VERSION 5.7 ;
BUSBITCHARS "[]" ;
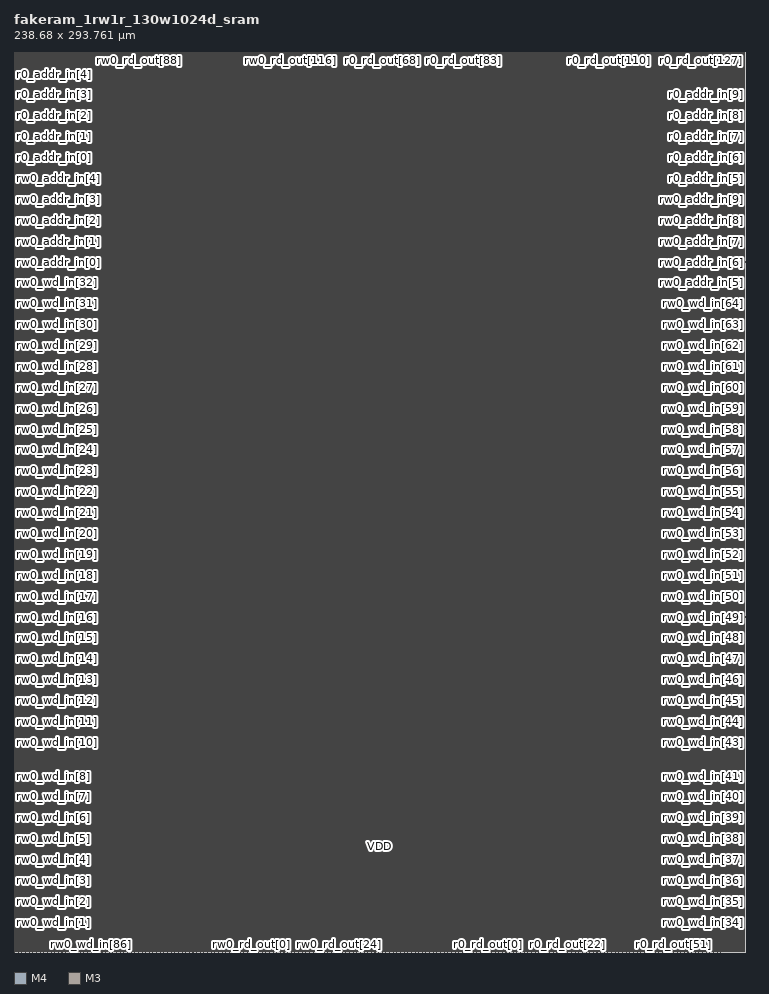
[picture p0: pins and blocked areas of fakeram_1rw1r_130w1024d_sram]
MACRO fakeram_1rw1r_130w1024d_sram
  FOREIGN fakeram_1rw1r_130w1024d_sram 0 0 ;
  SYMMETRY X Y R90 ;
  SIZE 238.680 BY 293.761 ;
  CLASS BLOCK ;
  PIN rw0_wd_in[0]
    DIRECTION INPUT ;
    USE SIGNAL ;
    SHAPE ABUTMENT ;
    PORT
      LAYER M4 ;
      RECT 0.000 0.276 0.072 0.300 ;
    END
  END rw0_wd_in[0]
  PIN rw0_wd_in[1]
    DIRECTION INPUT ;
    USE SIGNAL ;
    SHAPE ABUTMENT ;
    PORT
      LAYER M4 ;
      RECT 0.000 7.092 0.072 7.116 ;
    END
  END rw0_wd_in[1]
  PIN rw0_wd_in[2]
    DIRECTION INPUT ;
    USE SIGNAL ;
    SHAPE ABUTMENT ;
    PORT
      LAYER M4 ;
      RECT 0.000 13.908 0.072 13.932 ;
    END
  END rw0_wd_in[2]
  PIN rw0_wd_in[3]
    DIRECTION INPUT ;
    USE SIGNAL ;
    SHAPE ABUTMENT ;
    PORT
      LAYER M4 ;
      RECT 0.000 20.724 0.072 20.748 ;
    END
  END rw0_wd_in[3]
  PIN rw0_wd_in[4]
    DIRECTION INPUT ;
    USE SIGNAL ;
    SHAPE ABUTMENT ;
    PORT
      LAYER M4 ;
      RECT 0.000 27.540 0.072 27.564 ;
    END
  END rw0_wd_in[4]
  PIN rw0_wd_in[5]
    DIRECTION INPUT ;
    USE SIGNAL ;
    SHAPE ABUTMENT ;
    PORT
      LAYER M4 ;
      RECT 0.000 34.356 0.072 34.380 ;
    END
  END rw0_wd_in[5]
  PIN rw0_wd_in[6]
    DIRECTION INPUT ;
    USE SIGNAL ;
    SHAPE ABUTMENT ;
    PORT
      LAYER M4 ;
      RECT 0.000 41.172 0.072 41.196 ;
    END
  END rw0_wd_in[6]
  PIN rw0_wd_in[7]
    DIRECTION INPUT ;
    USE SIGNAL ;
    SHAPE ABUTMENT ;
    PORT
      LAYER M4 ;
      RECT 0.000 47.988 0.072 48.012 ;
    END
  END rw0_wd_in[7]
  PIN rw0_wd_in[8]
    DIRECTION INPUT ;
    USE SIGNAL ;
    SHAPE ABUTMENT ;
    PORT
      LAYER M4 ;
      RECT 0.000 54.804 0.072 54.828 ;
    END
  END rw0_wd_in[8]
  PIN rw0_wd_in[9]
    DIRECTION INPUT ;
    USE SIGNAL ;
    SHAPE ABUTMENT ;
    PORT
      LAYER M4 ;
      RECT 0.000 61.620 0.072 61.644 ;
    END
  END rw0_wd_in[9]
  PIN rw0_wd_in[10]
    DIRECTION INPUT ;
    USE SIGNAL ;
    SHAPE ABUTMENT ;
    PORT
      LAYER M4 ;
      RECT 0.000 68.436 0.072 68.460 ;
    END
  END rw0_wd_in[10]
  PIN rw0_wd_in[11]
    DIRECTION INPUT ;
    USE SIGNAL ;
    SHAPE ABUTMENT ;
    PORT
      LAYER M4 ;
      RECT 0.000 75.252 0.072 75.276 ;
    END
  END rw0_wd_in[11]
  PIN rw0_wd_in[12]
    DIRECTION INPUT ;
    USE SIGNAL ;
    SHAPE ABUTMENT ;
    PORT
      LAYER M4 ;
      RECT 0.000 82.068 0.072 82.092 ;
    END
  END rw0_wd_in[12]
  PIN rw0_wd_in[13]
    DIRECTION INPUT ;
    USE SIGNAL ;
    SHAPE ABUTMENT ;
    PORT
      LAYER M4 ;
      RECT 0.000 88.884 0.072 88.908 ;
    END
  END rw0_wd_in[13]
  PIN rw0_wd_in[14]
    DIRECTION INPUT ;
    USE SIGNAL ;
    SHAPE ABUTMENT ;
    PORT
      LAYER M4 ;
      RECT 0.000 95.700 0.072 95.724 ;
    END
  END rw0_wd_in[14]
  PIN rw0_wd_in[15]
    DIRECTION INPUT ;
    USE SIGNAL ;
    SHAPE ABUTMENT ;
    PORT
      LAYER M4 ;
      RECT 0.000 102.516 0.072 102.540 ;
    END
  END rw0_wd_in[15]
  PIN rw0_wd_in[16]
    DIRECTION INPUT ;
    USE SIGNAL ;
    SHAPE ABUTMENT ;
    PORT
      LAYER M4 ;
      RECT 0.000 109.332 0.072 109.356 ;
    END
  END rw0_wd_in[16]
  PIN rw0_wd_in[17]
    DIRECTION INPUT ;
    USE SIGNAL ;
    SHAPE ABUTMENT ;
    PORT
      LAYER M4 ;
      RECT 0.000 116.148 0.072 116.172 ;
    END
  END rw0_wd_in[17]
  PIN rw0_wd_in[18]
    DIRECTION INPUT ;
    USE SIGNAL ;
    SHAPE ABUTMENT ;
    PORT
      LAYER M4 ;
      RECT 0.000 122.964 0.072 122.988 ;
    END
  END rw0_wd_in[18]
  PIN rw0_wd_in[19]
    DIRECTION INPUT ;
    USE SIGNAL ;
    SHAPE ABUTMENT ;
    PORT
      LAYER M4 ;
      RECT 0.000 129.780 0.072 129.804 ;
    END
  END rw0_wd_in[19]
  PIN rw0_wd_in[20]
    DIRECTION INPUT ;
    USE SIGNAL ;
    SHAPE ABUTMENT ;
    PORT
      LAYER M4 ;
      RECT 0.000 136.596 0.072 136.620 ;
    END
  END rw0_wd_in[20]
  PIN rw0_wd_in[21]
    DIRECTION INPUT ;
    USE SIGNAL ;
    SHAPE ABUTMENT ;
    PORT
      LAYER M4 ;
      RECT 0.000 143.412 0.072 143.436 ;
    END
  END rw0_wd_in[21]
  PIN rw0_wd_in[22]
    DIRECTION INPUT ;
    USE SIGNAL ;
    SHAPE ABUTMENT ;
    PORT
      LAYER M4 ;
      RECT 0.000 150.228 0.072 150.252 ;
    END
  END rw0_wd_in[22]
  PIN rw0_wd_in[23]
    DIRECTION INPUT ;
    USE SIGNAL ;
    SHAPE ABUTMENT ;
    PORT
      LAYER M4 ;
      RECT 0.000 157.044 0.072 157.068 ;
    END
  END rw0_wd_in[23]
  PIN rw0_wd_in[24]
    DIRECTION INPUT ;
    USE SIGNAL ;
    SHAPE ABUTMENT ;
    PORT
      LAYER M4 ;
      RECT 0.000 163.860 0.072 163.884 ;
    END
  END rw0_wd_in[24]
  PIN rw0_wd_in[25]
    DIRECTION INPUT ;
    USE SIGNAL ;
    SHAPE ABUTMENT ;
    PORT
      LAYER M4 ;
      RECT 0.000 170.676 0.072 170.700 ;
    END
  END rw0_wd_in[25]
  PIN rw0_wd_in[26]
    DIRECTION INPUT ;
    USE SIGNAL ;
    SHAPE ABUTMENT ;
    PORT
      LAYER M4 ;
      RECT 0.000 177.492 0.072 177.516 ;
    END
  END rw0_wd_in[26]
  PIN rw0_wd_in[27]
    DIRECTION INPUT ;
    USE SIGNAL ;
    SHAPE ABUTMENT ;
    PORT
      LAYER M4 ;
      RECT 0.000 184.308 0.072 184.332 ;
    END
  END rw0_wd_in[27]
  PIN rw0_wd_in[28]
    DIRECTION INPUT ;
    USE SIGNAL ;
    SHAPE ABUTMENT ;
    PORT
      LAYER M4 ;
      RECT 0.000 191.124 0.072 191.148 ;
    END
  END rw0_wd_in[28]
  PIN rw0_wd_in[29]
    DIRECTION INPUT ;
    USE SIGNAL ;
    SHAPE ABUTMENT ;
    PORT
      LAYER M4 ;
      RECT 0.000 197.940 0.072 197.964 ;
    END
  END rw0_wd_in[29]
  PIN rw0_wd_in[30]
    DIRECTION INPUT ;
    USE SIGNAL ;
    SHAPE ABUTMENT ;
    PORT
      LAYER M4 ;
      RECT 0.000 204.756 0.072 204.780 ;
    END
  END rw0_wd_in[30]
  PIN rw0_wd_in[31]
    DIRECTION INPUT ;
    USE SIGNAL ;
    SHAPE ABUTMENT ;
    PORT
      LAYER M4 ;
      RECT 0.000 211.572 0.072 211.596 ;
    END
  END rw0_wd_in[31]
  PIN rw0_wd_in[32]
    DIRECTION INPUT ;
    USE SIGNAL ;
    SHAPE ABUTMENT ;
    PORT
      LAYER M4 ;
      RECT 0.000 218.388 0.072 218.412 ;
    END
  END rw0_wd_in[32]
  PIN rw0_wd_in[33]
    DIRECTION INPUT ;
    USE SIGNAL ;
    SHAPE ABUTMENT ;
    PORT
      LAYER M4 ;
      RECT 238.608 0.276 238.680 0.300 ;
    END
  END rw0_wd_in[33]
  PIN rw0_wd_in[34]
    DIRECTION INPUT ;
    USE SIGNAL ;
    SHAPE ABUTMENT ;
    PORT
      LAYER M4 ;
      RECT 238.608 7.092 238.680 7.116 ;
    END
  END rw0_wd_in[34]
  PIN rw0_wd_in[35]
    DIRECTION INPUT ;
    USE SIGNAL ;
    SHAPE ABUTMENT ;
    PORT
      LAYER M4 ;
      RECT 238.608 13.908 238.680 13.932 ;
    END
  END rw0_wd_in[35]
  PIN rw0_wd_in[36]
    DIRECTION INPUT ;
    USE SIGNAL ;
    SHAPE ABUTMENT ;
    PORT
      LAYER M4 ;
      RECT 238.608 20.724 238.680 20.748 ;
    END
  END rw0_wd_in[36]
  PIN rw0_wd_in[37]
    DIRECTION INPUT ;
    USE SIGNAL ;
    SHAPE ABUTMENT ;
    PORT
      LAYER M4 ;
      RECT 238.608 27.540 238.680 27.564 ;
    END
  END rw0_wd_in[37]
  PIN rw0_wd_in[38]
    DIRECTION INPUT ;
    USE SIGNAL ;
    SHAPE ABUTMENT ;
    PORT
      LAYER M4 ;
      RECT 238.608 34.356 238.680 34.380 ;
    END
  END rw0_wd_in[38]
  PIN rw0_wd_in[39]
    DIRECTION INPUT ;
    USE SIGNAL ;
    SHAPE ABUTMENT ;
    PORT
      LAYER M4 ;
      RECT 238.608 41.172 238.680 41.196 ;
    END
  END rw0_wd_in[39]
  PIN rw0_wd_in[40]
    DIRECTION INPUT ;
    USE SIGNAL ;
    SHAPE ABUTMENT ;
    PORT
      LAYER M4 ;
      RECT 238.608 47.988 238.680 48.012 ;
    END
  END rw0_wd_in[40]
  PIN rw0_wd_in[41]
    DIRECTION INPUT ;
    USE SIGNAL ;
    SHAPE ABUTMENT ;
    PORT
      LAYER M4 ;
      RECT 238.608 54.804 238.680 54.828 ;
    END
  END rw0_wd_in[41]
  PIN rw0_wd_in[42]
    DIRECTION INPUT ;
    USE SIGNAL ;
    SHAPE ABUTMENT ;
    PORT
      LAYER M4 ;
      RECT 238.608 61.620 238.680 61.644 ;
    END
  END rw0_wd_in[42]
  PIN rw0_wd_in[43]
    DIRECTION INPUT ;
    USE SIGNAL ;
    SHAPE ABUTMENT ;
    PORT
      LAYER M4 ;
      RECT 238.608 68.436 238.680 68.460 ;
    END
  END rw0_wd_in[43]
  PIN rw0_wd_in[44]
    DIRECTION INPUT ;
    USE SIGNAL ;
    SHAPE ABUTMENT ;
    PORT
      LAYER M4 ;
      RECT 238.608 75.252 238.680 75.276 ;
    END
  END rw0_wd_in[44]
  PIN rw0_wd_in[45]
    DIRECTION INPUT ;
    USE SIGNAL ;
    SHAPE ABUTMENT ;
    PORT
      LAYER M4 ;
      RECT 238.608 82.068 238.680 82.092 ;
    END
  END rw0_wd_in[45]
  PIN rw0_wd_in[46]
    DIRECTION INPUT ;
    USE SIGNAL ;
    SHAPE ABUTMENT ;
    PORT
      LAYER M4 ;
      RECT 238.608 88.884 238.680 88.908 ;
    END
  END rw0_wd_in[46]
  PIN rw0_wd_in[47]
    DIRECTION INPUT ;
    USE SIGNAL ;
    SHAPE ABUTMENT ;
    PORT
      LAYER M4 ;
      RECT 238.608 95.700 238.680 95.724 ;
    END
  END rw0_wd_in[47]
  PIN rw0_wd_in[48]
    DIRECTION INPUT ;
    USE SIGNAL ;
    SHAPE ABUTMENT ;
    PORT
      LAYER M4 ;
      RECT 238.608 102.516 238.680 102.540 ;
    END
  END rw0_wd_in[48]
  PIN rw0_wd_in[49]
    DIRECTION INPUT ;
    USE SIGNAL ;
    SHAPE ABUTMENT ;
    PORT
      LAYER M4 ;
      RECT 238.608 109.332 238.680 109.356 ;
    END
  END rw0_wd_in[49]
  PIN rw0_wd_in[50]
    DIRECTION INPUT ;
    USE SIGNAL ;
    SHAPE ABUTMENT ;
    PORT
      LAYER M4 ;
      RECT 238.608 116.148 238.680 116.172 ;
    END
  END rw0_wd_in[50]
  PIN rw0_wd_in[51]
    DIRECTION INPUT ;
    USE SIGNAL ;
    SHAPE ABUTMENT ;
    PORT
      LAYER M4 ;
      RECT 238.608 122.964 238.680 122.988 ;
    END
  END rw0_wd_in[51]
  PIN rw0_wd_in[52]
    DIRECTION INPUT ;
    USE SIGNAL ;
    SHAPE ABUTMENT ;
    PORT
      LAYER M4 ;
      RECT 238.608 129.780 238.680 129.804 ;
    END
  END rw0_wd_in[52]
  PIN rw0_wd_in[53]
    DIRECTION INPUT ;
    USE SIGNAL ;
    SHAPE ABUTMENT ;
    PORT
      LAYER M4 ;
      RECT 238.608 136.596 238.680 136.620 ;
    END
  END rw0_wd_in[53]
  PIN rw0_wd_in[54]
    DIRECTION INPUT ;
    USE SIGNAL ;
    SHAPE ABUTMENT ;
    PORT
      LAYER M4 ;
      RECT 238.608 143.412 238.680 143.436 ;
    END
  END rw0_wd_in[54]
  PIN rw0_wd_in[55]
    DIRECTION INPUT ;
    USE SIGNAL ;
    SHAPE ABUTMENT ;
    PORT
      LAYER M4 ;
      RECT 238.608 150.228 238.680 150.252 ;
    END
  END rw0_wd_in[55]
  PIN rw0_wd_in[56]
    DIRECTION INPUT ;
    USE SIGNAL ;
    SHAPE ABUTMENT ;
    PORT
      LAYER M4 ;
      RECT 238.608 157.044 238.680 157.068 ;
    END
  END rw0_wd_in[56]
  PIN rw0_wd_in[57]
    DIRECTION INPUT ;
    USE SIGNAL ;
    SHAPE ABUTMENT ;
    PORT
      LAYER M4 ;
      RECT 238.608 163.860 238.680 163.884 ;
    END
  END rw0_wd_in[57]
  PIN rw0_wd_in[58]
    DIRECTION INPUT ;
    USE SIGNAL ;
    SHAPE ABUTMENT ;
    PORT
      LAYER M4 ;
      RECT 238.608 170.676 238.680 170.700 ;
    END
  END rw0_wd_in[58]
  PIN rw0_wd_in[59]
    DIRECTION INPUT ;
    USE SIGNAL ;
    SHAPE ABUTMENT ;
    PORT
      LAYER M4 ;
      RECT 238.608 177.492 238.680 177.516 ;
    END
  END rw0_wd_in[59]
  PIN rw0_wd_in[60]
    DIRECTION INPUT ;
    USE SIGNAL ;
    SHAPE ABUTMENT ;
    PORT
      LAYER M4 ;
      RECT 238.608 184.308 238.680 184.332 ;
    END
  END rw0_wd_in[60]
  PIN rw0_wd_in[61]
    DIRECTION INPUT ;
    USE SIGNAL ;
    SHAPE ABUTMENT ;
    PORT
      LAYER M4 ;
      RECT 238.608 191.124 238.680 191.148 ;
    END
  END rw0_wd_in[61]
  PIN rw0_wd_in[62]
    DIRECTION INPUT ;
    USE SIGNAL ;
    SHAPE ABUTMENT ;
    PORT
      LAYER M4 ;
      RECT 238.608 197.940 238.680 197.964 ;
    END
  END rw0_wd_in[62]
  PIN rw0_wd_in[63]
    DIRECTION INPUT ;
    USE SIGNAL ;
    SHAPE ABUTMENT ;
    PORT
      LAYER M4 ;
      RECT 238.608 204.756 238.680 204.780 ;
    END
  END rw0_wd_in[63]
  PIN rw0_wd_in[64]
    DIRECTION INPUT ;
    USE SIGNAL ;
    SHAPE ABUTMENT ;
    PORT
      LAYER M4 ;
      RECT 238.608 211.572 238.680 211.596 ;
    END
  END rw0_wd_in[64]
  PIN rw0_wd_in[65]
    DIRECTION INPUT ;
    USE SIGNAL ;
    SHAPE ABUTMENT ;
    PORT
      LAYER M3 ;
      RECT 0.207 0.000 0.225 0.054 ;
    END
  END rw0_wd_in[65]
  PIN rw0_wd_in[66]
    DIRECTION INPUT ;
    USE SIGNAL ;
    SHAPE ABUTMENT ;
    PORT
      LAYER M3 ;
      RECT 1.395 0.000 1.413 0.054 ;
    END
  END rw0_wd_in[66]
  PIN rw0_wd_in[67]
    DIRECTION INPUT ;
    USE SIGNAL ;
    SHAPE ABUTMENT ;
    PORT
      LAYER M3 ;
      RECT 2.583 0.000 2.601 0.054 ;
    END
  END rw0_wd_in[67]
  PIN rw0_wd_in[68]
    DIRECTION INPUT ;
    USE SIGNAL ;
    SHAPE ABUTMENT ;
    PORT
      LAYER M3 ;
      RECT 3.771 0.000 3.789 0.054 ;
    END
  END rw0_wd_in[68]
  PIN rw0_wd_in[69]
    DIRECTION INPUT ;
    USE SIGNAL ;
    SHAPE ABUTMENT ;
    PORT
      LAYER M3 ;
      RECT 4.959 0.000 4.977 0.054 ;
    END
  END rw0_wd_in[69]
  PIN rw0_wd_in[70]
    DIRECTION INPUT ;
    USE SIGNAL ;
    SHAPE ABUTMENT ;
    PORT
      LAYER M3 ;
      RECT 6.147 0.000 6.165 0.054 ;
    END
  END rw0_wd_in[70]
  PIN rw0_wd_in[71]
    DIRECTION INPUT ;
    USE SIGNAL ;
    SHAPE ABUTMENT ;
    PORT
      LAYER M3 ;
      RECT 7.335 0.000 7.353 0.054 ;
    END
  END rw0_wd_in[71]
  PIN rw0_wd_in[72]
    DIRECTION INPUT ;
    USE SIGNAL ;
    SHAPE ABUTMENT ;
    PORT
      LAYER M3 ;
      RECT 8.523 0.000 8.541 0.054 ;
    END
  END rw0_wd_in[72]
  PIN rw0_wd_in[73]
    DIRECTION INPUT ;
    USE SIGNAL ;
    SHAPE ABUTMENT ;
    PORT
      LAYER M3 ;
      RECT 9.711 0.000 9.729 0.054 ;
    END
  END rw0_wd_in[73]
  PIN rw0_wd_in[74]
    DIRECTION INPUT ;
    USE SIGNAL ;
    SHAPE ABUTMENT ;
    PORT
      LAYER M3 ;
      RECT 10.899 0.000 10.917 0.054 ;
    END
  END rw0_wd_in[74]
  PIN rw0_wd_in[75]
    DIRECTION INPUT ;
    USE SIGNAL ;
    SHAPE ABUTMENT ;
    PORT
      LAYER M3 ;
      RECT 12.087 0.000 12.105 0.054 ;
    END
  END rw0_wd_in[75]
  PIN rw0_wd_in[76]
    DIRECTION INPUT ;
    USE SIGNAL ;
    SHAPE ABUTMENT ;
    PORT
      LAYER M3 ;
      RECT 13.275 0.000 13.293 0.054 ;
    END
  END rw0_wd_in[76]
  PIN rw0_wd_in[77]
    DIRECTION INPUT ;
    USE SIGNAL ;
    SHAPE ABUTMENT ;
    PORT
      LAYER M3 ;
      RECT 14.463 0.000 14.481 0.054 ;
    END
  END rw0_wd_in[77]
  PIN rw0_wd_in[78]
    DIRECTION INPUT ;
    USE SIGNAL ;
    SHAPE ABUTMENT ;
    PORT
      LAYER M3 ;
      RECT 15.651 0.000 15.669 0.054 ;
    END
  END rw0_wd_in[78]
  PIN rw0_wd_in[79]
    DIRECTION INPUT ;
    USE SIGNAL ;
    SHAPE ABUTMENT ;
    PORT
      LAYER M3 ;
      RECT 16.839 0.000 16.857 0.054 ;
    END
  END rw0_wd_in[79]
  PIN rw0_wd_in[80]
    DIRECTION INPUT ;
    USE SIGNAL ;
    SHAPE ABUTMENT ;
    PORT
      LAYER M3 ;
      RECT 18.027 0.000 18.045 0.054 ;
    END
  END rw0_wd_in[80]
  PIN rw0_wd_in[81]
    DIRECTION INPUT ;
    USE SIGNAL ;
    SHAPE ABUTMENT ;
    PORT
      LAYER M3 ;
      RECT 19.215 0.000 19.233 0.054 ;
    END
  END rw0_wd_in[81]
  PIN rw0_wd_in[82]
    DIRECTION INPUT ;
    USE SIGNAL ;
    SHAPE ABUTMENT ;
    PORT
      LAYER M3 ;
      RECT 20.403 0.000 20.421 0.054 ;
    END
  END rw0_wd_in[82]
  PIN rw0_wd_in[83]
    DIRECTION INPUT ;
    USE SIGNAL ;
    SHAPE ABUTMENT ;
    PORT
      LAYER M3 ;
      RECT 21.591 0.000 21.609 0.054 ;
    END
  END rw0_wd_in[83]
  PIN rw0_wd_in[84]
    DIRECTION INPUT ;
    USE SIGNAL ;
    SHAPE ABUTMENT ;
    PORT
      LAYER M3 ;
      RECT 22.779 0.000 22.797 0.054 ;
    END
  END rw0_wd_in[84]
  PIN rw0_wd_in[85]
    DIRECTION INPUT ;
    USE SIGNAL ;
    SHAPE ABUTMENT ;
    PORT
      LAYER M3 ;
      RECT 23.967 0.000 23.985 0.054 ;
    END
  END rw0_wd_in[85]
  PIN rw0_wd_in[86]
    DIRECTION INPUT ;
    USE SIGNAL ;
    SHAPE ABUTMENT ;
    PORT
      LAYER M3 ;
      RECT 25.155 0.000 25.173 0.054 ;
    END
  END rw0_wd_in[86]
  PIN rw0_wd_in[87]
    DIRECTION INPUT ;
    USE SIGNAL ;
    SHAPE ABUTMENT ;
    PORT
      LAYER M3 ;
      RECT 26.343 0.000 26.361 0.054 ;
    END
  END rw0_wd_in[87]
  PIN rw0_wd_in[88]
    DIRECTION INPUT ;
    USE SIGNAL ;
    SHAPE ABUTMENT ;
    PORT
      LAYER M3 ;
      RECT 27.531 0.000 27.549 0.054 ;
    END
  END rw0_wd_in[88]
  PIN rw0_wd_in[89]
    DIRECTION INPUT ;
    USE SIGNAL ;
    SHAPE ABUTMENT ;
    PORT
      LAYER M3 ;
      RECT 28.719 0.000 28.737 0.054 ;
    END
  END rw0_wd_in[89]
  PIN rw0_wd_in[90]
    DIRECTION INPUT ;
    USE SIGNAL ;
    SHAPE ABUTMENT ;
    PORT
      LAYER M3 ;
      RECT 29.907 0.000 29.925 0.054 ;
    END
  END rw0_wd_in[90]
  PIN rw0_wd_in[91]
    DIRECTION INPUT ;
    USE SIGNAL ;
    SHAPE ABUTMENT ;
    PORT
      LAYER M3 ;
      RECT 31.095 0.000 31.113 0.054 ;
    END
  END rw0_wd_in[91]
  PIN rw0_wd_in[92]
    DIRECTION INPUT ;
    USE SIGNAL ;
    SHAPE ABUTMENT ;
    PORT
      LAYER M3 ;
      RECT 32.283 0.000 32.301 0.054 ;
    END
  END rw0_wd_in[92]
  PIN rw0_wd_in[93]
    DIRECTION INPUT ;
    USE SIGNAL ;
    SHAPE ABUTMENT ;
    PORT
      LAYER M3 ;
      RECT 33.471 0.000 33.489 0.054 ;
    END
  END rw0_wd_in[93]
  PIN rw0_wd_in[94]
    DIRECTION INPUT ;
    USE SIGNAL ;
    SHAPE ABUTMENT ;
    PORT
      LAYER M3 ;
      RECT 34.659 0.000 34.677 0.054 ;
    END
  END rw0_wd_in[94]
  PIN rw0_wd_in[95]
    DIRECTION INPUT ;
    USE SIGNAL ;
    SHAPE ABUTMENT ;
    PORT
      LAYER M3 ;
      RECT 35.847 0.000 35.865 0.054 ;
    END
  END rw0_wd_in[95]
  PIN rw0_wd_in[96]
    DIRECTION INPUT ;
    USE SIGNAL ;
    SHAPE ABUTMENT ;
    PORT
      LAYER M3 ;
      RECT 37.035 0.000 37.053 0.054 ;
    END
  END rw0_wd_in[96]
  PIN rw0_wd_in[97]
    DIRECTION INPUT ;
    USE SIGNAL ;
    SHAPE ABUTMENT ;
    PORT
      LAYER M3 ;
      RECT 38.223 0.000 38.241 0.054 ;
    END
  END rw0_wd_in[97]
  PIN rw0_wd_in[98]
    DIRECTION INPUT ;
    USE SIGNAL ;
    SHAPE ABUTMENT ;
    PORT
      LAYER M3 ;
      RECT 39.411 0.000 39.429 0.054 ;
    END
  END rw0_wd_in[98]
  PIN rw0_wd_in[99]
    DIRECTION INPUT ;
    USE SIGNAL ;
    SHAPE ABUTMENT ;
    PORT
      LAYER M3 ;
      RECT 40.599 0.000 40.617 0.054 ;
    END
  END rw0_wd_in[99]
  PIN rw0_wd_in[100]
    DIRECTION INPUT ;
    USE SIGNAL ;
    SHAPE ABUTMENT ;
    PORT
      LAYER M3 ;
      RECT 41.787 0.000 41.805 0.054 ;
    END
  END rw0_wd_in[100]
  PIN rw0_wd_in[101]
    DIRECTION INPUT ;
    USE SIGNAL ;
    SHAPE ABUTMENT ;
    PORT
      LAYER M3 ;
      RECT 42.975 0.000 42.993 0.054 ;
    END
  END rw0_wd_in[101]
  PIN rw0_wd_in[102]
    DIRECTION INPUT ;
    USE SIGNAL ;
    SHAPE ABUTMENT ;
    PORT
      LAYER M3 ;
      RECT 44.163 0.000 44.181 0.054 ;
    END
  END rw0_wd_in[102]
  PIN rw0_wd_in[103]
    DIRECTION INPUT ;
    USE SIGNAL ;
    SHAPE ABUTMENT ;
    PORT
      LAYER M3 ;
      RECT 45.351 0.000 45.369 0.054 ;
    END
  END rw0_wd_in[103]
  PIN rw0_wd_in[104]
    DIRECTION INPUT ;
    USE SIGNAL ;
    SHAPE ABUTMENT ;
    PORT
      LAYER M3 ;
      RECT 46.539 0.000 46.557 0.054 ;
    END
  END rw0_wd_in[104]
  PIN rw0_wd_in[105]
    DIRECTION INPUT ;
    USE SIGNAL ;
    SHAPE ABUTMENT ;
    PORT
      LAYER M3 ;
      RECT 47.727 0.000 47.745 0.054 ;
    END
  END rw0_wd_in[105]
  PIN rw0_wd_in[106]
    DIRECTION INPUT ;
    USE SIGNAL ;
    SHAPE ABUTMENT ;
    PORT
      LAYER M3 ;
      RECT 48.915 0.000 48.933 0.054 ;
    END
  END rw0_wd_in[106]
  PIN rw0_wd_in[107]
    DIRECTION INPUT ;
    USE SIGNAL ;
    SHAPE ABUTMENT ;
    PORT
      LAYER M3 ;
      RECT 50.103 0.000 50.121 0.054 ;
    END
  END rw0_wd_in[107]
  PIN rw0_wd_in[108]
    DIRECTION INPUT ;
    USE SIGNAL ;
    SHAPE ABUTMENT ;
    PORT
      LAYER M3 ;
      RECT 51.291 0.000 51.309 0.054 ;
    END
  END rw0_wd_in[108]
  PIN rw0_wd_in[109]
    DIRECTION INPUT ;
    USE SIGNAL ;
    SHAPE ABUTMENT ;
    PORT
      LAYER M3 ;
      RECT 52.479 0.000 52.497 0.054 ;
    END
  END rw0_wd_in[109]
  PIN rw0_wd_in[110]
    DIRECTION INPUT ;
    USE SIGNAL ;
    SHAPE ABUTMENT ;
    PORT
      LAYER M3 ;
      RECT 53.667 0.000 53.685 0.054 ;
    END
  END rw0_wd_in[110]
  PIN rw0_wd_in[111]
    DIRECTION INPUT ;
    USE SIGNAL ;
    SHAPE ABUTMENT ;
    PORT
      LAYER M3 ;
      RECT 54.855 0.000 54.873 0.054 ;
    END
  END rw0_wd_in[111]
  PIN rw0_wd_in[112]
    DIRECTION INPUT ;
    USE SIGNAL ;
    SHAPE ABUTMENT ;
    PORT
      LAYER M3 ;
      RECT 56.043 0.000 56.061 0.054 ;
    END
  END rw0_wd_in[112]
  PIN rw0_wd_in[113]
    DIRECTION INPUT ;
    USE SIGNAL ;
    SHAPE ABUTMENT ;
    PORT
      LAYER M3 ;
      RECT 57.231 0.000 57.249 0.054 ;
    END
  END rw0_wd_in[113]
  PIN rw0_wd_in[114]
    DIRECTION INPUT ;
    USE SIGNAL ;
    SHAPE ABUTMENT ;
    PORT
      LAYER M3 ;
      RECT 58.419 0.000 58.437 0.054 ;
    END
  END rw0_wd_in[114]
  PIN rw0_wd_in[115]
    DIRECTION INPUT ;
    USE SIGNAL ;
    SHAPE ABUTMENT ;
    PORT
      LAYER M3 ;
      RECT 59.607 0.000 59.625 0.054 ;
    END
  END rw0_wd_in[115]
  PIN rw0_wd_in[116]
    DIRECTION INPUT ;
    USE SIGNAL ;
    SHAPE ABUTMENT ;
    PORT
      LAYER M3 ;
      RECT 60.795 0.000 60.813 0.054 ;
    END
  END rw0_wd_in[116]
  PIN rw0_wd_in[117]
    DIRECTION INPUT ;
    USE SIGNAL ;
    SHAPE ABUTMENT ;
    PORT
      LAYER M3 ;
      RECT 61.983 0.000 62.001 0.054 ;
    END
  END rw0_wd_in[117]
  PIN rw0_wd_in[118]
    DIRECTION INPUT ;
    USE SIGNAL ;
    SHAPE ABUTMENT ;
    PORT
      LAYER M3 ;
      RECT 63.171 0.000 63.189 0.054 ;
    END
  END rw0_wd_in[118]
  PIN rw0_wd_in[119]
    DIRECTION INPUT ;
    USE SIGNAL ;
    SHAPE ABUTMENT ;
    PORT
      LAYER M3 ;
      RECT 64.359 0.000 64.377 0.054 ;
    END
  END rw0_wd_in[119]
  PIN rw0_wd_in[120]
    DIRECTION INPUT ;
    USE SIGNAL ;
    SHAPE ABUTMENT ;
    PORT
      LAYER M3 ;
      RECT 65.547 0.000 65.565 0.054 ;
    END
  END rw0_wd_in[120]
  PIN rw0_wd_in[121]
    DIRECTION INPUT ;
    USE SIGNAL ;
    SHAPE ABUTMENT ;
    PORT
      LAYER M3 ;
      RECT 66.735 0.000 66.753 0.054 ;
    END
  END rw0_wd_in[121]
  PIN rw0_wd_in[122]
    DIRECTION INPUT ;
    USE SIGNAL ;
    SHAPE ABUTMENT ;
    PORT
      LAYER M3 ;
      RECT 67.923 0.000 67.941 0.054 ;
    END
  END rw0_wd_in[122]
  PIN rw0_wd_in[123]
    DIRECTION INPUT ;
    USE SIGNAL ;
    SHAPE ABUTMENT ;
    PORT
      LAYER M3 ;
      RECT 69.111 0.000 69.129 0.054 ;
    END
  END rw0_wd_in[123]
  PIN rw0_wd_in[124]
    DIRECTION INPUT ;
    USE SIGNAL ;
    SHAPE ABUTMENT ;
    PORT
      LAYER M3 ;
      RECT 70.299 0.000 70.317 0.054 ;
    END
  END rw0_wd_in[124]
  PIN rw0_wd_in[125]
    DIRECTION INPUT ;
    USE SIGNAL ;
    SHAPE ABUTMENT ;
    PORT
      LAYER M3 ;
      RECT 71.487 0.000 71.505 0.054 ;
    END
  END rw0_wd_in[125]
  PIN rw0_wd_in[126]
    DIRECTION INPUT ;
    USE SIGNAL ;
    SHAPE ABUTMENT ;
    PORT
      LAYER M3 ;
      RECT 72.675 0.000 72.693 0.054 ;
    END
  END rw0_wd_in[126]
  PIN rw0_wd_in[127]
    DIRECTION INPUT ;
    USE SIGNAL ;
    SHAPE ABUTMENT ;
    PORT
      LAYER M3 ;
      RECT 73.863 0.000 73.881 0.054 ;
    END
  END rw0_wd_in[127]
  PIN rw0_wd_in[128]
    DIRECTION INPUT ;
    USE SIGNAL ;
    SHAPE ABUTMENT ;
    PORT
      LAYER M3 ;
      RECT 75.051 0.000 75.069 0.054 ;
    END
  END rw0_wd_in[128]
  PIN rw0_wd_in[129]
    DIRECTION INPUT ;
    USE SIGNAL ;
    SHAPE ABUTMENT ;
    PORT
      LAYER M3 ;
      RECT 76.239 0.000 76.257 0.054 ;
    END
  END rw0_wd_in[129]
  PIN rw0_rd_out[0]
    DIRECTION OUTPUT ;
    USE SIGNAL ;
    SHAPE ABUTMENT ;
    PORT
      LAYER M3 ;
      RECT 77.427 0.000 77.445 0.054 ;
    END
  END rw0_rd_out[0]
  PIN rw0_rd_out[1]
    DIRECTION OUTPUT ;
    USE SIGNAL ;
    SHAPE ABUTMENT ;
    PORT
      LAYER M3 ;
      RECT 78.615 0.000 78.633 0.054 ;
    END
  END rw0_rd_out[1]
  PIN rw0_rd_out[2]
    DIRECTION OUTPUT ;
    USE SIGNAL ;
    SHAPE ABUTMENT ;
    PORT
      LAYER M3 ;
      RECT 79.803 0.000 79.821 0.054 ;
    END
  END rw0_rd_out[2]
  PIN rw0_rd_out[3]
    DIRECTION OUTPUT ;
    USE SIGNAL ;
    SHAPE ABUTMENT ;
    PORT
      LAYER M3 ;
      RECT 80.991 0.000 81.009 0.054 ;
    END
  END rw0_rd_out[3]
  PIN rw0_rd_out[4]
    DIRECTION OUTPUT ;
    USE SIGNAL ;
    SHAPE ABUTMENT ;
    PORT
      LAYER M3 ;
      RECT 82.179 0.000 82.197 0.054 ;
    END
  END rw0_rd_out[4]
  PIN rw0_rd_out[5]
    DIRECTION OUTPUT ;
    USE SIGNAL ;
    SHAPE ABUTMENT ;
    PORT
      LAYER M3 ;
      RECT 83.367 0.000 83.385 0.054 ;
    END
  END rw0_rd_out[5]
  PIN rw0_rd_out[6]
    DIRECTION OUTPUT ;
    USE SIGNAL ;
    SHAPE ABUTMENT ;
    PORT
      LAYER M3 ;
      RECT 84.555 0.000 84.573 0.054 ;
    END
  END rw0_rd_out[6]
  PIN rw0_rd_out[7]
    DIRECTION OUTPUT ;
    USE SIGNAL ;
    SHAPE ABUTMENT ;
    PORT
      LAYER M3 ;
      RECT 85.743 0.000 85.761 0.054 ;
    END
  END rw0_rd_out[7]
  PIN rw0_rd_out[8]
    DIRECTION OUTPUT ;
    USE SIGNAL ;
    SHAPE ABUTMENT ;
    PORT
      LAYER M3 ;
      RECT 86.931 0.000 86.949 0.054 ;
    END
  END rw0_rd_out[8]
  PIN rw0_rd_out[9]
    DIRECTION OUTPUT ;
    USE SIGNAL ;
    SHAPE ABUTMENT ;
    PORT
      LAYER M3 ;
      RECT 88.119 0.000 88.137 0.054 ;
    END
  END rw0_rd_out[9]
  PIN rw0_rd_out[10]
    DIRECTION OUTPUT ;
    USE SIGNAL ;
    SHAPE ABUTMENT ;
    PORT
      LAYER M3 ;
      RECT 89.307 0.000 89.325 0.054 ;
    END
  END rw0_rd_out[10]
  PIN rw0_rd_out[11]
    DIRECTION OUTPUT ;
    USE SIGNAL ;
    SHAPE ABUTMENT ;
    PORT
      LAYER M3 ;
      RECT 90.495 0.000 90.513 0.054 ;
    END
  END rw0_rd_out[11]
  PIN rw0_rd_out[12]
    DIRECTION OUTPUT ;
    USE SIGNAL ;
    SHAPE ABUTMENT ;
    PORT
      LAYER M3 ;
      RECT 91.683 0.000 91.701 0.054 ;
    END
  END rw0_rd_out[12]
  PIN rw0_rd_out[13]
    DIRECTION OUTPUT ;
    USE SIGNAL ;
    SHAPE ABUTMENT ;
    PORT
      LAYER M3 ;
      RECT 92.871 0.000 92.889 0.054 ;
    END
  END rw0_rd_out[13]
  PIN rw0_rd_out[14]
    DIRECTION OUTPUT ;
    USE SIGNAL ;
    SHAPE ABUTMENT ;
    PORT
      LAYER M3 ;
      RECT 94.059 0.000 94.077 0.054 ;
    END
  END rw0_rd_out[14]
  PIN rw0_rd_out[15]
    DIRECTION OUTPUT ;
    USE SIGNAL ;
    SHAPE ABUTMENT ;
    PORT
      LAYER M3 ;
      RECT 95.247 0.000 95.265 0.054 ;
    END
  END rw0_rd_out[15]
  PIN rw0_rd_out[16]
    DIRECTION OUTPUT ;
    USE SIGNAL ;
    SHAPE ABUTMENT ;
    PORT
      LAYER M3 ;
      RECT 96.435 0.000 96.453 0.054 ;
    END
  END rw0_rd_out[16]
  PIN rw0_rd_out[17]
    DIRECTION OUTPUT ;
    USE SIGNAL ;
    SHAPE ABUTMENT ;
    PORT
      LAYER M3 ;
      RECT 97.623 0.000 97.641 0.054 ;
    END
  END rw0_rd_out[17]
  PIN rw0_rd_out[18]
    DIRECTION OUTPUT ;
    USE SIGNAL ;
    SHAPE ABUTMENT ;
    PORT
      LAYER M3 ;
      RECT 98.811 0.000 98.829 0.054 ;
    END
  END rw0_rd_out[18]
  PIN rw0_rd_out[19]
    DIRECTION OUTPUT ;
    USE SIGNAL ;
    SHAPE ABUTMENT ;
    PORT
      LAYER M3 ;
      RECT 99.999 0.000 100.017 0.054 ;
    END
  END rw0_rd_out[19]
  PIN rw0_rd_out[20]
    DIRECTION OUTPUT ;
    USE SIGNAL ;
    SHAPE ABUTMENT ;
    PORT
      LAYER M3 ;
      RECT 101.187 0.000 101.205 0.054 ;
    END
  END rw0_rd_out[20]
  PIN rw0_rd_out[21]
    DIRECTION OUTPUT ;
    USE SIGNAL ;
    SHAPE ABUTMENT ;
    PORT
      LAYER M3 ;
      RECT 102.375 0.000 102.393 0.054 ;
    END
  END rw0_rd_out[21]
  PIN rw0_rd_out[22]
    DIRECTION OUTPUT ;
    USE SIGNAL ;
    SHAPE ABUTMENT ;
    PORT
      LAYER M3 ;
      RECT 103.563 0.000 103.581 0.054 ;
    END
  END rw0_rd_out[22]
  PIN rw0_rd_out[23]
    DIRECTION OUTPUT ;
    USE SIGNAL ;
    SHAPE ABUTMENT ;
    PORT
      LAYER M3 ;
      RECT 104.751 0.000 104.769 0.054 ;
    END
  END rw0_rd_out[23]
  PIN rw0_rd_out[24]
    DIRECTION OUTPUT ;
    USE SIGNAL ;
    SHAPE ABUTMENT ;
    PORT
      LAYER M3 ;
      RECT 105.939 0.000 105.957 0.054 ;
    END
  END rw0_rd_out[24]
  PIN rw0_rd_out[25]
    DIRECTION OUTPUT ;
    USE SIGNAL ;
    SHAPE ABUTMENT ;
    PORT
      LAYER M3 ;
      RECT 107.127 0.000 107.145 0.054 ;
    END
  END rw0_rd_out[25]
  PIN rw0_rd_out[26]
    DIRECTION OUTPUT ;
    USE SIGNAL ;
    SHAPE ABUTMENT ;
    PORT
      LAYER M3 ;
      RECT 108.315 0.000 108.333 0.054 ;
    END
  END rw0_rd_out[26]
  PIN rw0_rd_out[27]
    DIRECTION OUTPUT ;
    USE SIGNAL ;
    SHAPE ABUTMENT ;
    PORT
      LAYER M3 ;
      RECT 109.503 0.000 109.521 0.054 ;
    END
  END rw0_rd_out[27]
  PIN rw0_rd_out[28]
    DIRECTION OUTPUT ;
    USE SIGNAL ;
    SHAPE ABUTMENT ;
    PORT
      LAYER M3 ;
      RECT 110.691 0.000 110.709 0.054 ;
    END
  END rw0_rd_out[28]
  PIN rw0_rd_out[29]
    DIRECTION OUTPUT ;
    USE SIGNAL ;
    SHAPE ABUTMENT ;
    PORT
      LAYER M3 ;
      RECT 111.879 0.000 111.897 0.054 ;
    END
  END rw0_rd_out[29]
  PIN rw0_rd_out[30]
    DIRECTION OUTPUT ;
    USE SIGNAL ;
    SHAPE ABUTMENT ;
    PORT
      LAYER M3 ;
      RECT 113.067 0.000 113.085 0.054 ;
    END
  END rw0_rd_out[30]
  PIN rw0_rd_out[31]
    DIRECTION OUTPUT ;
    USE SIGNAL ;
    SHAPE ABUTMENT ;
    PORT
      LAYER M3 ;
      RECT 114.255 0.000 114.273 0.054 ;
    END
  END rw0_rd_out[31]
  PIN rw0_rd_out[32]
    DIRECTION OUTPUT ;
    USE SIGNAL ;
    SHAPE ABUTMENT ;
    PORT
      LAYER M3 ;
      RECT 115.443 0.000 115.461 0.054 ;
    END
  END rw0_rd_out[32]
  PIN rw0_rd_out[33]
    DIRECTION OUTPUT ;
    USE SIGNAL ;
    SHAPE ABUTMENT ;
    PORT
      LAYER M3 ;
      RECT 116.631 0.000 116.649 0.054 ;
    END
  END rw0_rd_out[33]
  PIN rw0_rd_out[34]
    DIRECTION OUTPUT ;
    USE SIGNAL ;
    SHAPE ABUTMENT ;
    PORT
      LAYER M3 ;
      RECT 117.819 0.000 117.837 0.054 ;
    END
  END rw0_rd_out[34]
  PIN rw0_rd_out[35]
    DIRECTION OUTPUT ;
    USE SIGNAL ;
    SHAPE ABUTMENT ;
    PORT
      LAYER M3 ;
      RECT 119.007 0.000 119.025 0.054 ;
    END
  END rw0_rd_out[35]
  PIN rw0_rd_out[36]
    DIRECTION OUTPUT ;
    USE SIGNAL ;
    SHAPE ABUTMENT ;
    PORT
      LAYER M3 ;
      RECT 120.195 0.000 120.213 0.054 ;
    END
  END rw0_rd_out[36]
  PIN rw0_rd_out[37]
    DIRECTION OUTPUT ;
    USE SIGNAL ;
    SHAPE ABUTMENT ;
    PORT
      LAYER M3 ;
      RECT 121.383 0.000 121.401 0.054 ;
    END
  END rw0_rd_out[37]
  PIN rw0_rd_out[38]
    DIRECTION OUTPUT ;
    USE SIGNAL ;
    SHAPE ABUTMENT ;
    PORT
      LAYER M3 ;
      RECT 122.571 0.000 122.589 0.054 ;
    END
  END rw0_rd_out[38]
  PIN rw0_rd_out[39]
    DIRECTION OUTPUT ;
    USE SIGNAL ;
    SHAPE ABUTMENT ;
    PORT
      LAYER M3 ;
      RECT 123.759 0.000 123.777 0.054 ;
    END
  END rw0_rd_out[39]
  PIN rw0_rd_out[40]
    DIRECTION OUTPUT ;
    USE SIGNAL ;
    SHAPE ABUTMENT ;
    PORT
      LAYER M3 ;
      RECT 124.947 0.000 124.965 0.054 ;
    END
  END rw0_rd_out[40]
  PIN rw0_rd_out[41]
    DIRECTION OUTPUT ;
    USE SIGNAL ;
    SHAPE ABUTMENT ;
    PORT
      LAYER M3 ;
      RECT 126.135 0.000 126.153 0.054 ;
    END
  END rw0_rd_out[41]
  PIN rw0_rd_out[42]
    DIRECTION OUTPUT ;
    USE SIGNAL ;
    SHAPE ABUTMENT ;
    PORT
      LAYER M3 ;
      RECT 127.323 0.000 127.341 0.054 ;
    END
  END rw0_rd_out[42]
  PIN rw0_rd_out[43]
    DIRECTION OUTPUT ;
    USE SIGNAL ;
    SHAPE ABUTMENT ;
    PORT
      LAYER M3 ;
      RECT 128.511 0.000 128.529 0.054 ;
    END
  END rw0_rd_out[43]
  PIN rw0_rd_out[44]
    DIRECTION OUTPUT ;
    USE SIGNAL ;
    SHAPE ABUTMENT ;
    PORT
      LAYER M3 ;
      RECT 129.699 0.000 129.717 0.054 ;
    END
  END rw0_rd_out[44]
  PIN rw0_rd_out[45]
    DIRECTION OUTPUT ;
    USE SIGNAL ;
    SHAPE ABUTMENT ;
    PORT
      LAYER M3 ;
      RECT 130.887 0.000 130.905 0.054 ;
    END
  END rw0_rd_out[45]
  PIN rw0_rd_out[46]
    DIRECTION OUTPUT ;
    USE SIGNAL ;
    SHAPE ABUTMENT ;
    PORT
      LAYER M3 ;
      RECT 132.075 0.000 132.093 0.054 ;
    END
  END rw0_rd_out[46]
  PIN rw0_rd_out[47]
    DIRECTION OUTPUT ;
    USE SIGNAL ;
    SHAPE ABUTMENT ;
    PORT
      LAYER M3 ;
      RECT 133.263 0.000 133.281 0.054 ;
    END
  END rw0_rd_out[47]
  PIN rw0_rd_out[48]
    DIRECTION OUTPUT ;
    USE SIGNAL ;
    SHAPE ABUTMENT ;
    PORT
      LAYER M3 ;
      RECT 134.451 0.000 134.469 0.054 ;
    END
  END rw0_rd_out[48]
  PIN rw0_rd_out[49]
    DIRECTION OUTPUT ;
    USE SIGNAL ;
    SHAPE ABUTMENT ;
    PORT
      LAYER M3 ;
      RECT 135.639 0.000 135.657 0.054 ;
    END
  END rw0_rd_out[49]
  PIN rw0_rd_out[50]
    DIRECTION OUTPUT ;
    USE SIGNAL ;
    SHAPE ABUTMENT ;
    PORT
      LAYER M3 ;
      RECT 136.827 0.000 136.845 0.054 ;
    END
  END rw0_rd_out[50]
  PIN rw0_rd_out[51]
    DIRECTION OUTPUT ;
    USE SIGNAL ;
    SHAPE ABUTMENT ;
    PORT
      LAYER M3 ;
      RECT 138.015 0.000 138.033 0.054 ;
    END
  END rw0_rd_out[51]
  PIN rw0_rd_out[52]
    DIRECTION OUTPUT ;
    USE SIGNAL ;
    SHAPE ABUTMENT ;
    PORT
      LAYER M3 ;
      RECT 139.203 0.000 139.221 0.054 ;
    END
  END rw0_rd_out[52]
  PIN rw0_rd_out[53]
    DIRECTION OUTPUT ;
    USE SIGNAL ;
    SHAPE ABUTMENT ;
    PORT
      LAYER M3 ;
      RECT 140.391 0.000 140.409 0.054 ;
    END
  END rw0_rd_out[53]
  PIN rw0_rd_out[54]
    DIRECTION OUTPUT ;
    USE SIGNAL ;
    SHAPE ABUTMENT ;
    PORT
      LAYER M3 ;
      RECT 141.579 0.000 141.597 0.054 ;
    END
  END rw0_rd_out[54]
  PIN rw0_rd_out[55]
    DIRECTION OUTPUT ;
    USE SIGNAL ;
    SHAPE ABUTMENT ;
    PORT
      LAYER M3 ;
      RECT 142.767 0.000 142.785 0.054 ;
    END
  END rw0_rd_out[55]
  PIN rw0_rd_out[56]
    DIRECTION OUTPUT ;
    USE SIGNAL ;
    SHAPE ABUTMENT ;
    PORT
      LAYER M3 ;
      RECT 143.955 0.000 143.973 0.054 ;
    END
  END rw0_rd_out[56]
  PIN rw0_rd_out[57]
    DIRECTION OUTPUT ;
    USE SIGNAL ;
    SHAPE ABUTMENT ;
    PORT
      LAYER M3 ;
      RECT 145.143 0.000 145.161 0.054 ;
    END
  END rw0_rd_out[57]
  PIN rw0_rd_out[58]
    DIRECTION OUTPUT ;
    USE SIGNAL ;
    SHAPE ABUTMENT ;
    PORT
      LAYER M3 ;
      RECT 146.331 0.000 146.349 0.054 ;
    END
  END rw0_rd_out[58]
  PIN rw0_rd_out[59]
    DIRECTION OUTPUT ;
    USE SIGNAL ;
    SHAPE ABUTMENT ;
    PORT
      LAYER M3 ;
      RECT 147.519 0.000 147.537 0.054 ;
    END
  END rw0_rd_out[59]
  PIN rw0_rd_out[60]
    DIRECTION OUTPUT ;
    USE SIGNAL ;
    SHAPE ABUTMENT ;
    PORT
      LAYER M3 ;
      RECT 148.707 0.000 148.725 0.054 ;
    END
  END rw0_rd_out[60]
  PIN rw0_rd_out[61]
    DIRECTION OUTPUT ;
    USE SIGNAL ;
    SHAPE ABUTMENT ;
    PORT
      LAYER M3 ;
      RECT 149.895 0.000 149.913 0.054 ;
    END
  END rw0_rd_out[61]
  PIN rw0_rd_out[62]
    DIRECTION OUTPUT ;
    USE SIGNAL ;
    SHAPE ABUTMENT ;
    PORT
      LAYER M3 ;
      RECT 151.083 0.000 151.101 0.054 ;
    END
  END rw0_rd_out[62]
  PIN rw0_rd_out[63]
    DIRECTION OUTPUT ;
    USE SIGNAL ;
    SHAPE ABUTMENT ;
    PORT
      LAYER M3 ;
      RECT 152.271 0.000 152.289 0.054 ;
    END
  END rw0_rd_out[63]
  PIN rw0_rd_out[64]
    DIRECTION OUTPUT ;
    USE SIGNAL ;
    SHAPE ABUTMENT ;
    PORT
      LAYER M3 ;
      RECT 153.459 0.000 153.477 0.054 ;
    END
  END rw0_rd_out[64]
  PIN rw0_rd_out[65]
    DIRECTION OUTPUT ;
    USE SIGNAL ;
    SHAPE ABUTMENT ;
    PORT
      LAYER M3 ;
      RECT 0.207 293.707 0.225 293.761 ;
    END
  END rw0_rd_out[65]
  PIN rw0_rd_out[66]
    DIRECTION OUTPUT ;
    USE SIGNAL ;
    SHAPE ABUTMENT ;
    PORT
      LAYER M3 ;
      RECT 1.971 293.707 1.989 293.761 ;
    END
  END rw0_rd_out[66]
  PIN rw0_rd_out[67]
    DIRECTION OUTPUT ;
    USE SIGNAL ;
    SHAPE ABUTMENT ;
    PORT
      LAYER M3 ;
      RECT 3.735 293.707 3.753 293.761 ;
    END
  END rw0_rd_out[67]
  PIN rw0_rd_out[68]
    DIRECTION OUTPUT ;
    USE SIGNAL ;
    SHAPE ABUTMENT ;
    PORT
      LAYER M3 ;
      RECT 5.499 293.707 5.517 293.761 ;
    END
  END rw0_rd_out[68]
  PIN rw0_rd_out[69]
    DIRECTION OUTPUT ;
    USE SIGNAL ;
    SHAPE ABUTMENT ;
    PORT
      LAYER M3 ;
      RECT 7.263 293.707 7.281 293.761 ;
    END
  END rw0_rd_out[69]
  PIN rw0_rd_out[70]
    DIRECTION OUTPUT ;
    USE SIGNAL ;
    SHAPE ABUTMENT ;
    PORT
      LAYER M3 ;
      RECT 9.027 293.707 9.045 293.761 ;
    END
  END rw0_rd_out[70]
  PIN rw0_rd_out[71]
    DIRECTION OUTPUT ;
    USE SIGNAL ;
    SHAPE ABUTMENT ;
    PORT
      LAYER M3 ;
      RECT 10.791 293.707 10.809 293.761 ;
    END
  END rw0_rd_out[71]
  PIN rw0_rd_out[72]
    DIRECTION OUTPUT ;
    USE SIGNAL ;
    SHAPE ABUTMENT ;
    PORT
      LAYER M3 ;
      RECT 12.555 293.707 12.573 293.761 ;
    END
  END rw0_rd_out[72]
  PIN rw0_rd_out[73]
    DIRECTION OUTPUT ;
    USE SIGNAL ;
    SHAPE ABUTMENT ;
    PORT
      LAYER M3 ;
      RECT 14.319 293.707 14.337 293.761 ;
    END
  END rw0_rd_out[73]
  PIN rw0_rd_out[74]
    DIRECTION OUTPUT ;
    USE SIGNAL ;
    SHAPE ABUTMENT ;
    PORT
      LAYER M3 ;
      RECT 16.083 293.707 16.101 293.761 ;
    END
  END rw0_rd_out[74]
  PIN rw0_rd_out[75]
    DIRECTION OUTPUT ;
    USE SIGNAL ;
    SHAPE ABUTMENT ;
    PORT
      LAYER M3 ;
      RECT 17.847 293.707 17.865 293.761 ;
    END
  END rw0_rd_out[75]
  PIN rw0_rd_out[76]
    DIRECTION OUTPUT ;
    USE SIGNAL ;
    SHAPE ABUTMENT ;
    PORT
      LAYER M3 ;
      RECT 19.611 293.707 19.629 293.761 ;
    END
  END rw0_rd_out[76]
  PIN rw0_rd_out[77]
    DIRECTION OUTPUT ;
    USE SIGNAL ;
    SHAPE ABUTMENT ;
    PORT
      LAYER M3 ;
      RECT 21.375 293.707 21.393 293.761 ;
    END
  END rw0_rd_out[77]
  PIN rw0_rd_out[78]
    DIRECTION OUTPUT ;
    USE SIGNAL ;
    SHAPE ABUTMENT ;
    PORT
      LAYER M3 ;
      RECT 23.139 293.707 23.157 293.761 ;
    END
  END rw0_rd_out[78]
  PIN rw0_rd_out[79]
    DIRECTION OUTPUT ;
    USE SIGNAL ;
    SHAPE ABUTMENT ;
    PORT
      LAYER M3 ;
      RECT 24.903 293.707 24.921 293.761 ;
    END
  END rw0_rd_out[79]
  PIN rw0_rd_out[80]
    DIRECTION OUTPUT ;
    USE SIGNAL ;
    SHAPE ABUTMENT ;
    PORT
      LAYER M3 ;
      RECT 26.667 293.707 26.685 293.761 ;
    END
  END rw0_rd_out[80]
  PIN rw0_rd_out[81]
    DIRECTION OUTPUT ;
    USE SIGNAL ;
    SHAPE ABUTMENT ;
    PORT
      LAYER M3 ;
      RECT 28.431 293.707 28.449 293.761 ;
    END
  END rw0_rd_out[81]
  PIN rw0_rd_out[82]
    DIRECTION OUTPUT ;
    USE SIGNAL ;
    SHAPE ABUTMENT ;
    PORT
      LAYER M3 ;
      RECT 30.195 293.707 30.213 293.761 ;
    END
  END rw0_rd_out[82]
  PIN rw0_rd_out[83]
    DIRECTION OUTPUT ;
    USE SIGNAL ;
    SHAPE ABUTMENT ;
    PORT
      LAYER M3 ;
      RECT 31.959 293.707 31.977 293.761 ;
    END
  END rw0_rd_out[83]
  PIN rw0_rd_out[84]
    DIRECTION OUTPUT ;
    USE SIGNAL ;
    SHAPE ABUTMENT ;
    PORT
      LAYER M3 ;
      RECT 33.723 293.707 33.741 293.761 ;
    END
  END rw0_rd_out[84]
  PIN rw0_rd_out[85]
    DIRECTION OUTPUT ;
    USE SIGNAL ;
    SHAPE ABUTMENT ;
    PORT
      LAYER M3 ;
      RECT 35.487 293.707 35.505 293.761 ;
    END
  END rw0_rd_out[85]
  PIN rw0_rd_out[86]
    DIRECTION OUTPUT ;
    USE SIGNAL ;
    SHAPE ABUTMENT ;
    PORT
      LAYER M3 ;
      RECT 37.251 293.707 37.269 293.761 ;
    END
  END rw0_rd_out[86]
  PIN rw0_rd_out[87]
    DIRECTION OUTPUT ;
    USE SIGNAL ;
    SHAPE ABUTMENT ;
    PORT
      LAYER M3 ;
      RECT 39.015 293.707 39.033 293.761 ;
    END
  END rw0_rd_out[87]
  PIN rw0_rd_out[88]
    DIRECTION OUTPUT ;
    USE SIGNAL ;
    SHAPE ABUTMENT ;
    PORT
      LAYER M3 ;
      RECT 40.779 293.707 40.797 293.761 ;
    END
  END rw0_rd_out[88]
  PIN rw0_rd_out[89]
    DIRECTION OUTPUT ;
    USE SIGNAL ;
    SHAPE ABUTMENT ;
    PORT
      LAYER M3 ;
      RECT 42.543 293.707 42.561 293.761 ;
    END
  END rw0_rd_out[89]
  PIN rw0_rd_out[90]
    DIRECTION OUTPUT ;
    USE SIGNAL ;
    SHAPE ABUTMENT ;
    PORT
      LAYER M3 ;
      RECT 44.307 293.707 44.325 293.761 ;
    END
  END rw0_rd_out[90]
  PIN rw0_rd_out[91]
    DIRECTION OUTPUT ;
    USE SIGNAL ;
    SHAPE ABUTMENT ;
    PORT
      LAYER M3 ;
      RECT 46.071 293.707 46.089 293.761 ;
    END
  END rw0_rd_out[91]
  PIN rw0_rd_out[92]
    DIRECTION OUTPUT ;
    USE SIGNAL ;
    SHAPE ABUTMENT ;
    PORT
      LAYER M3 ;
      RECT 47.835 293.707 47.853 293.761 ;
    END
  END rw0_rd_out[92]
  PIN rw0_rd_out[93]
    DIRECTION OUTPUT ;
    USE SIGNAL ;
    SHAPE ABUTMENT ;
    PORT
      LAYER M3 ;
      RECT 49.599 293.707 49.617 293.761 ;
    END
  END rw0_rd_out[93]
  PIN rw0_rd_out[94]
    DIRECTION OUTPUT ;
    USE SIGNAL ;
    SHAPE ABUTMENT ;
    PORT
      LAYER M3 ;
      RECT 51.363 293.707 51.381 293.761 ;
    END
  END rw0_rd_out[94]
  PIN rw0_rd_out[95]
    DIRECTION OUTPUT ;
    USE SIGNAL ;
    SHAPE ABUTMENT ;
    PORT
      LAYER M3 ;
      RECT 53.127 293.707 53.145 293.761 ;
    END
  END rw0_rd_out[95]
  PIN rw0_rd_out[96]
    DIRECTION OUTPUT ;
    USE SIGNAL ;
    SHAPE ABUTMENT ;
    PORT
      LAYER M3 ;
      RECT 54.891 293.707 54.909 293.761 ;
    END
  END rw0_rd_out[96]
  PIN rw0_rd_out[97]
    DIRECTION OUTPUT ;
    USE SIGNAL ;
    SHAPE ABUTMENT ;
    PORT
      LAYER M3 ;
      RECT 56.655 293.707 56.673 293.761 ;
    END
  END rw0_rd_out[97]
  PIN rw0_rd_out[98]
    DIRECTION OUTPUT ;
    USE SIGNAL ;
    SHAPE ABUTMENT ;
    PORT
      LAYER M3 ;
      RECT 58.419 293.707 58.437 293.761 ;
    END
  END rw0_rd_out[98]
  PIN rw0_rd_out[99]
    DIRECTION OUTPUT ;
    USE SIGNAL ;
    SHAPE ABUTMENT ;
    PORT
      LAYER M3 ;
      RECT 60.183 293.707 60.201 293.761 ;
    END
  END rw0_rd_out[99]
  PIN rw0_rd_out[100]
    DIRECTION OUTPUT ;
    USE SIGNAL ;
    SHAPE ABUTMENT ;
    PORT
      LAYER M3 ;
      RECT 61.947 293.707 61.965 293.761 ;
    END
  END rw0_rd_out[100]
  PIN rw0_rd_out[101]
    DIRECTION OUTPUT ;
    USE SIGNAL ;
    SHAPE ABUTMENT ;
    PORT
      LAYER M3 ;
      RECT 63.711 293.707 63.729 293.761 ;
    END
  END rw0_rd_out[101]
  PIN rw0_rd_out[102]
    DIRECTION OUTPUT ;
    USE SIGNAL ;
    SHAPE ABUTMENT ;
    PORT
      LAYER M3 ;
      RECT 65.475 293.707 65.493 293.761 ;
    END
  END rw0_rd_out[102]
  PIN rw0_rd_out[103]
    DIRECTION OUTPUT ;
    USE SIGNAL ;
    SHAPE ABUTMENT ;
    PORT
      LAYER M3 ;
      RECT 67.239 293.707 67.257 293.761 ;
    END
  END rw0_rd_out[103]
  PIN rw0_rd_out[104]
    DIRECTION OUTPUT ;
    USE SIGNAL ;
    SHAPE ABUTMENT ;
    PORT
      LAYER M3 ;
      RECT 69.003 293.707 69.021 293.761 ;
    END
  END rw0_rd_out[104]
  PIN rw0_rd_out[105]
    DIRECTION OUTPUT ;
    USE SIGNAL ;
    SHAPE ABUTMENT ;
    PORT
      LAYER M3 ;
      RECT 70.767 293.707 70.785 293.761 ;
    END
  END rw0_rd_out[105]
  PIN rw0_rd_out[106]
    DIRECTION OUTPUT ;
    USE SIGNAL ;
    SHAPE ABUTMENT ;
    PORT
      LAYER M3 ;
      RECT 72.531 293.707 72.549 293.761 ;
    END
  END rw0_rd_out[106]
  PIN rw0_rd_out[107]
    DIRECTION OUTPUT ;
    USE SIGNAL ;
    SHAPE ABUTMENT ;
    PORT
      LAYER M3 ;
      RECT 74.295 293.707 74.313 293.761 ;
    END
  END rw0_rd_out[107]
  PIN rw0_rd_out[108]
    DIRECTION OUTPUT ;
    USE SIGNAL ;
    SHAPE ABUTMENT ;
    PORT
      LAYER M3 ;
      RECT 76.059 293.707 76.077 293.761 ;
    END
  END rw0_rd_out[108]
  PIN rw0_rd_out[109]
    DIRECTION OUTPUT ;
    USE SIGNAL ;
    SHAPE ABUTMENT ;
    PORT
      LAYER M3 ;
      RECT 77.823 293.707 77.841 293.761 ;
    END
  END rw0_rd_out[109]
  PIN rw0_rd_out[110]
    DIRECTION OUTPUT ;
    USE SIGNAL ;
    SHAPE ABUTMENT ;
    PORT
      LAYER M3 ;
      RECT 79.587 293.707 79.605 293.761 ;
    END
  END rw0_rd_out[110]
  PIN rw0_rd_out[111]
    DIRECTION OUTPUT ;
    USE SIGNAL ;
    SHAPE ABUTMENT ;
    PORT
      LAYER M3 ;
      RECT 81.351 293.707 81.369 293.761 ;
    END
  END rw0_rd_out[111]
  PIN rw0_rd_out[112]
    DIRECTION OUTPUT ;
    USE SIGNAL ;
    SHAPE ABUTMENT ;
    PORT
      LAYER M3 ;
      RECT 83.115 293.707 83.133 293.761 ;
    END
  END rw0_rd_out[112]
  PIN rw0_rd_out[113]
    DIRECTION OUTPUT ;
    USE SIGNAL ;
    SHAPE ABUTMENT ;
    PORT
      LAYER M3 ;
      RECT 84.879 293.707 84.897 293.761 ;
    END
  END rw0_rd_out[113]
  PIN rw0_rd_out[114]
    DIRECTION OUTPUT ;
    USE SIGNAL ;
    SHAPE ABUTMENT ;
    PORT
      LAYER M3 ;
      RECT 86.643 293.707 86.661 293.761 ;
    END
  END rw0_rd_out[114]
  PIN rw0_rd_out[115]
    DIRECTION OUTPUT ;
    USE SIGNAL ;
    SHAPE ABUTMENT ;
    PORT
      LAYER M3 ;
      RECT 88.407 293.707 88.425 293.761 ;
    END
  END rw0_rd_out[115]
  PIN rw0_rd_out[116]
    DIRECTION OUTPUT ;
    USE SIGNAL ;
    SHAPE ABUTMENT ;
    PORT
      LAYER M3 ;
      RECT 90.171 293.707 90.189 293.761 ;
    END
  END rw0_rd_out[116]
  PIN rw0_rd_out[117]
    DIRECTION OUTPUT ;
    USE SIGNAL ;
    SHAPE ABUTMENT ;
    PORT
      LAYER M3 ;
      RECT 91.935 293.707 91.953 293.761 ;
    END
  END rw0_rd_out[117]
  PIN rw0_rd_out[118]
    DIRECTION OUTPUT ;
    USE SIGNAL ;
    SHAPE ABUTMENT ;
    PORT
      LAYER M3 ;
      RECT 93.699 293.707 93.717 293.761 ;
    END
  END rw0_rd_out[118]
  PIN rw0_rd_out[119]
    DIRECTION OUTPUT ;
    USE SIGNAL ;
    SHAPE ABUTMENT ;
    PORT
      LAYER M3 ;
      RECT 95.463 293.707 95.481 293.761 ;
    END
  END rw0_rd_out[119]
  PIN rw0_rd_out[120]
    DIRECTION OUTPUT ;
    USE SIGNAL ;
    SHAPE ABUTMENT ;
    PORT
      LAYER M3 ;
      RECT 97.227 293.707 97.245 293.761 ;
    END
  END rw0_rd_out[120]
  PIN rw0_rd_out[121]
    DIRECTION OUTPUT ;
    USE SIGNAL ;
    SHAPE ABUTMENT ;
    PORT
      LAYER M3 ;
      RECT 98.991 293.707 99.009 293.761 ;
    END
  END rw0_rd_out[121]
  PIN rw0_rd_out[122]
    DIRECTION OUTPUT ;
    USE SIGNAL ;
    SHAPE ABUTMENT ;
    PORT
      LAYER M3 ;
      RECT 100.755 293.707 100.773 293.761 ;
    END
  END rw0_rd_out[122]
  PIN rw0_rd_out[123]
    DIRECTION OUTPUT ;
    USE SIGNAL ;
    SHAPE ABUTMENT ;
    PORT
      LAYER M3 ;
      RECT 102.519 293.707 102.537 293.761 ;
    END
  END rw0_rd_out[123]
  PIN rw0_rd_out[124]
    DIRECTION OUTPUT ;
    USE SIGNAL ;
    SHAPE ABUTMENT ;
    PORT
      LAYER M3 ;
      RECT 104.283 293.707 104.301 293.761 ;
    END
  END rw0_rd_out[124]
  PIN rw0_rd_out[125]
    DIRECTION OUTPUT ;
    USE SIGNAL ;
    SHAPE ABUTMENT ;
    PORT
      LAYER M3 ;
      RECT 106.047 293.707 106.065 293.761 ;
    END
  END rw0_rd_out[125]
  PIN rw0_rd_out[126]
    DIRECTION OUTPUT ;
    USE SIGNAL ;
    SHAPE ABUTMENT ;
    PORT
      LAYER M3 ;
      RECT 107.811 293.707 107.829 293.761 ;
    END
  END rw0_rd_out[126]
  PIN rw0_rd_out[127]
    DIRECTION OUTPUT ;
    USE SIGNAL ;
    SHAPE ABUTMENT ;
    PORT
      LAYER M3 ;
      RECT 109.575 293.707 109.593 293.761 ;
    END
  END rw0_rd_out[127]
  PIN rw0_rd_out[128]
    DIRECTION OUTPUT ;
    USE SIGNAL ;
    SHAPE ABUTMENT ;
    PORT
      LAYER M3 ;
      RECT 111.339 293.707 111.357 293.761 ;
    END
  END rw0_rd_out[128]
  PIN rw0_rd_out[129]
    DIRECTION OUTPUT ;
    USE SIGNAL ;
    SHAPE ABUTMENT ;
    PORT
      LAYER M3 ;
      RECT 113.103 293.707 113.121 293.761 ;
    END
  END rw0_rd_out[129]
  PIN r0_rd_out[0]
    DIRECTION OUTPUT ;
    USE SIGNAL ;
    SHAPE ABUTMENT ;
    PORT
      LAYER M3 ;
      RECT 154.647 0.000 154.665 0.054 ;
    END
  END r0_rd_out[0]
  PIN r0_rd_out[1]
    DIRECTION OUTPUT ;
    USE SIGNAL ;
    SHAPE ABUTMENT ;
    PORT
      LAYER M3 ;
      RECT 155.835 0.000 155.853 0.054 ;
    END
  END r0_rd_out[1]
  PIN r0_rd_out[2]
    DIRECTION OUTPUT ;
    USE SIGNAL ;
    SHAPE ABUTMENT ;
    PORT
      LAYER M3 ;
      RECT 157.023 0.000 157.041 0.054 ;
    END
  END r0_rd_out[2]
  PIN r0_rd_out[3]
    DIRECTION OUTPUT ;
    USE SIGNAL ;
    SHAPE ABUTMENT ;
    PORT
      LAYER M3 ;
      RECT 158.211 0.000 158.229 0.054 ;
    END
  END r0_rd_out[3]
  PIN r0_rd_out[4]
    DIRECTION OUTPUT ;
    USE SIGNAL ;
    SHAPE ABUTMENT ;
    PORT
      LAYER M3 ;
      RECT 159.399 0.000 159.417 0.054 ;
    END
  END r0_rd_out[4]
  PIN r0_rd_out[5]
    DIRECTION OUTPUT ;
    USE SIGNAL ;
    SHAPE ABUTMENT ;
    PORT
      LAYER M3 ;
      RECT 160.587 0.000 160.605 0.054 ;
    END
  END r0_rd_out[5]
  PIN r0_rd_out[6]
    DIRECTION OUTPUT ;
    USE SIGNAL ;
    SHAPE ABUTMENT ;
    PORT
      LAYER M3 ;
      RECT 161.775 0.000 161.793 0.054 ;
    END
  END r0_rd_out[6]
  PIN r0_rd_out[7]
    DIRECTION OUTPUT ;
    USE SIGNAL ;
    SHAPE ABUTMENT ;
    PORT
      LAYER M3 ;
      RECT 162.963 0.000 162.981 0.054 ;
    END
  END r0_rd_out[7]
  PIN r0_rd_out[8]
    DIRECTION OUTPUT ;
    USE SIGNAL ;
    SHAPE ABUTMENT ;
    PORT
      LAYER M3 ;
      RECT 164.151 0.000 164.169 0.054 ;
    END
  END r0_rd_out[8]
  PIN r0_rd_out[9]
    DIRECTION OUTPUT ;
    USE SIGNAL ;
    SHAPE ABUTMENT ;
    PORT
      LAYER M3 ;
      RECT 165.339 0.000 165.357 0.054 ;
    END
  END r0_rd_out[9]
  PIN r0_rd_out[10]
    DIRECTION OUTPUT ;
    USE SIGNAL ;
    SHAPE ABUTMENT ;
    PORT
      LAYER M3 ;
      RECT 166.527 0.000 166.545 0.054 ;
    END
  END r0_rd_out[10]
  PIN r0_rd_out[11]
    DIRECTION OUTPUT ;
    USE SIGNAL ;
    SHAPE ABUTMENT ;
    PORT
      LAYER M3 ;
      RECT 167.715 0.000 167.733 0.054 ;
    END
  END r0_rd_out[11]
  PIN r0_rd_out[12]
    DIRECTION OUTPUT ;
    USE SIGNAL ;
    SHAPE ABUTMENT ;
    PORT
      LAYER M3 ;
      RECT 168.903 0.000 168.921 0.054 ;
    END
  END r0_rd_out[12]
  PIN r0_rd_out[13]
    DIRECTION OUTPUT ;
    USE SIGNAL ;
    SHAPE ABUTMENT ;
    PORT
      LAYER M3 ;
      RECT 170.091 0.000 170.109 0.054 ;
    END
  END r0_rd_out[13]
  PIN r0_rd_out[14]
    DIRECTION OUTPUT ;
    USE SIGNAL ;
    SHAPE ABUTMENT ;
    PORT
      LAYER M3 ;
      RECT 171.279 0.000 171.297 0.054 ;
    END
  END r0_rd_out[14]
  PIN r0_rd_out[15]
    DIRECTION OUTPUT ;
    USE SIGNAL ;
    SHAPE ABUTMENT ;
    PORT
      LAYER M3 ;
      RECT 172.467 0.000 172.485 0.054 ;
    END
  END r0_rd_out[15]
  PIN r0_rd_out[16]
    DIRECTION OUTPUT ;
    USE SIGNAL ;
    SHAPE ABUTMENT ;
    PORT
      LAYER M3 ;
      RECT 173.655 0.000 173.673 0.054 ;
    END
  END r0_rd_out[16]
  PIN r0_rd_out[17]
    DIRECTION OUTPUT ;
    USE SIGNAL ;
    SHAPE ABUTMENT ;
    PORT
      LAYER M3 ;
      RECT 174.843 0.000 174.861 0.054 ;
    END
  END r0_rd_out[17]
  PIN r0_rd_out[18]
    DIRECTION OUTPUT ;
    USE SIGNAL ;
    SHAPE ABUTMENT ;
    PORT
      LAYER M3 ;
      RECT 176.031 0.000 176.049 0.054 ;
    END
  END r0_rd_out[18]
  PIN r0_rd_out[19]
    DIRECTION OUTPUT ;
    USE SIGNAL ;
    SHAPE ABUTMENT ;
    PORT
      LAYER M3 ;
      RECT 177.219 0.000 177.237 0.054 ;
    END
  END r0_rd_out[19]
  PIN r0_rd_out[20]
    DIRECTION OUTPUT ;
    USE SIGNAL ;
    SHAPE ABUTMENT ;
    PORT
      LAYER M3 ;
      RECT 178.407 0.000 178.425 0.054 ;
    END
  END r0_rd_out[20]
  PIN r0_rd_out[21]
    DIRECTION OUTPUT ;
    USE SIGNAL ;
    SHAPE ABUTMENT ;
    PORT
      LAYER M3 ;
      RECT 179.595 0.000 179.613 0.054 ;
    END
  END r0_rd_out[21]
  PIN r0_rd_out[22]
    DIRECTION OUTPUT ;
    USE SIGNAL ;
    SHAPE ABUTMENT ;
    PORT
      LAYER M3 ;
      RECT 180.783 0.000 180.801 0.054 ;
    END
  END r0_rd_out[22]
  PIN r0_rd_out[23]
    DIRECTION OUTPUT ;
    USE SIGNAL ;
    SHAPE ABUTMENT ;
    PORT
      LAYER M3 ;
      RECT 181.971 0.000 181.989 0.054 ;
    END
  END r0_rd_out[23]
  PIN r0_rd_out[24]
    DIRECTION OUTPUT ;
    USE SIGNAL ;
    SHAPE ABUTMENT ;
    PORT
      LAYER M3 ;
      RECT 183.159 0.000 183.177 0.054 ;
    END
  END r0_rd_out[24]
  PIN r0_rd_out[25]
    DIRECTION OUTPUT ;
    USE SIGNAL ;
    SHAPE ABUTMENT ;
    PORT
      LAYER M3 ;
      RECT 184.347 0.000 184.365 0.054 ;
    END
  END r0_rd_out[25]
  PIN r0_rd_out[26]
    DIRECTION OUTPUT ;
    USE SIGNAL ;
    SHAPE ABUTMENT ;
    PORT
      LAYER M3 ;
      RECT 185.535 0.000 185.553 0.054 ;
    END
  END r0_rd_out[26]
  PIN r0_rd_out[27]
    DIRECTION OUTPUT ;
    USE SIGNAL ;
    SHAPE ABUTMENT ;
    PORT
      LAYER M3 ;
      RECT 186.723 0.000 186.741 0.054 ;
    END
  END r0_rd_out[27]
  PIN r0_rd_out[28]
    DIRECTION OUTPUT ;
    USE SIGNAL ;
    SHAPE ABUTMENT ;
    PORT
      LAYER M3 ;
      RECT 187.911 0.000 187.929 0.054 ;
    END
  END r0_rd_out[28]
  PIN r0_rd_out[29]
    DIRECTION OUTPUT ;
    USE SIGNAL ;
    SHAPE ABUTMENT ;
    PORT
      LAYER M3 ;
      RECT 189.099 0.000 189.117 0.054 ;
    END
  END r0_rd_out[29]
  PIN r0_rd_out[30]
    DIRECTION OUTPUT ;
    USE SIGNAL ;
    SHAPE ABUTMENT ;
    PORT
      LAYER M3 ;
      RECT 190.287 0.000 190.305 0.054 ;
    END
  END r0_rd_out[30]
  PIN r0_rd_out[31]
    DIRECTION OUTPUT ;
    USE SIGNAL ;
    SHAPE ABUTMENT ;
    PORT
      LAYER M3 ;
      RECT 191.475 0.000 191.493 0.054 ;
    END
  END r0_rd_out[31]
  PIN r0_rd_out[32]
    DIRECTION OUTPUT ;
    USE SIGNAL ;
    SHAPE ABUTMENT ;
    PORT
      LAYER M3 ;
      RECT 192.663 0.000 192.681 0.054 ;
    END
  END r0_rd_out[32]
  PIN r0_rd_out[33]
    DIRECTION OUTPUT ;
    USE SIGNAL ;
    SHAPE ABUTMENT ;
    PORT
      LAYER M3 ;
      RECT 193.851 0.000 193.869 0.054 ;
    END
  END r0_rd_out[33]
  PIN r0_rd_out[34]
    DIRECTION OUTPUT ;
    USE SIGNAL ;
    SHAPE ABUTMENT ;
    PORT
      LAYER M3 ;
      RECT 195.039 0.000 195.057 0.054 ;
    END
  END r0_rd_out[34]
  PIN r0_rd_out[35]
    DIRECTION OUTPUT ;
    USE SIGNAL ;
    SHAPE ABUTMENT ;
    PORT
      LAYER M3 ;
      RECT 196.227 0.000 196.245 0.054 ;
    END
  END r0_rd_out[35]
  PIN r0_rd_out[36]
    DIRECTION OUTPUT ;
    USE SIGNAL ;
    SHAPE ABUTMENT ;
    PORT
      LAYER M3 ;
      RECT 197.415 0.000 197.433 0.054 ;
    END
  END r0_rd_out[36]
  PIN r0_rd_out[37]
    DIRECTION OUTPUT ;
    USE SIGNAL ;
    SHAPE ABUTMENT ;
    PORT
      LAYER M3 ;
      RECT 198.603 0.000 198.621 0.054 ;
    END
  END r0_rd_out[37]
  PIN r0_rd_out[38]
    DIRECTION OUTPUT ;
    USE SIGNAL ;
    SHAPE ABUTMENT ;
    PORT
      LAYER M3 ;
      RECT 199.791 0.000 199.809 0.054 ;
    END
  END r0_rd_out[38]
  PIN r0_rd_out[39]
    DIRECTION OUTPUT ;
    USE SIGNAL ;
    SHAPE ABUTMENT ;
    PORT
      LAYER M3 ;
      RECT 200.979 0.000 200.997 0.054 ;
    END
  END r0_rd_out[39]
  PIN r0_rd_out[40]
    DIRECTION OUTPUT ;
    USE SIGNAL ;
    SHAPE ABUTMENT ;
    PORT
      LAYER M3 ;
      RECT 202.167 0.000 202.185 0.054 ;
    END
  END r0_rd_out[40]
  PIN r0_rd_out[41]
    DIRECTION OUTPUT ;
    USE SIGNAL ;
    SHAPE ABUTMENT ;
    PORT
      LAYER M3 ;
      RECT 203.355 0.000 203.373 0.054 ;
    END
  END r0_rd_out[41]
  PIN r0_rd_out[42]
    DIRECTION OUTPUT ;
    USE SIGNAL ;
    SHAPE ABUTMENT ;
    PORT
      LAYER M3 ;
      RECT 204.543 0.000 204.561 0.054 ;
    END
  END r0_rd_out[42]
  PIN r0_rd_out[43]
    DIRECTION OUTPUT ;
    USE SIGNAL ;
    SHAPE ABUTMENT ;
    PORT
      LAYER M3 ;
      RECT 205.731 0.000 205.749 0.054 ;
    END
  END r0_rd_out[43]
  PIN r0_rd_out[44]
    DIRECTION OUTPUT ;
    USE SIGNAL ;
    SHAPE ABUTMENT ;
    PORT
      LAYER M3 ;
      RECT 206.919 0.000 206.937 0.054 ;
    END
  END r0_rd_out[44]
  PIN r0_rd_out[45]
    DIRECTION OUTPUT ;
    USE SIGNAL ;
    SHAPE ABUTMENT ;
    PORT
      LAYER M3 ;
      RECT 208.107 0.000 208.125 0.054 ;
    END
  END r0_rd_out[45]
  PIN r0_rd_out[46]
    DIRECTION OUTPUT ;
    USE SIGNAL ;
    SHAPE ABUTMENT ;
    PORT
      LAYER M3 ;
      RECT 209.295 0.000 209.313 0.054 ;
    END
  END r0_rd_out[46]
  PIN r0_rd_out[47]
    DIRECTION OUTPUT ;
    USE SIGNAL ;
    SHAPE ABUTMENT ;
    PORT
      LAYER M3 ;
      RECT 210.483 0.000 210.501 0.054 ;
    END
  END r0_rd_out[47]
  PIN r0_rd_out[48]
    DIRECTION OUTPUT ;
    USE SIGNAL ;
    SHAPE ABUTMENT ;
    PORT
      LAYER M3 ;
      RECT 211.671 0.000 211.689 0.054 ;
    END
  END r0_rd_out[48]
  PIN r0_rd_out[49]
    DIRECTION OUTPUT ;
    USE SIGNAL ;
    SHAPE ABUTMENT ;
    PORT
      LAYER M3 ;
      RECT 212.859 0.000 212.877 0.054 ;
    END
  END r0_rd_out[49]
  PIN r0_rd_out[50]
    DIRECTION OUTPUT ;
    USE SIGNAL ;
    SHAPE ABUTMENT ;
    PORT
      LAYER M3 ;
      RECT 214.047 0.000 214.065 0.054 ;
    END
  END r0_rd_out[50]
  PIN r0_rd_out[51]
    DIRECTION OUTPUT ;
    USE SIGNAL ;
    SHAPE ABUTMENT ;
    PORT
      LAYER M3 ;
      RECT 215.235 0.000 215.253 0.054 ;
    END
  END r0_rd_out[51]
  PIN r0_rd_out[52]
    DIRECTION OUTPUT ;
    USE SIGNAL ;
    SHAPE ABUTMENT ;
    PORT
      LAYER M3 ;
      RECT 216.423 0.000 216.441 0.054 ;
    END
  END r0_rd_out[52]
  PIN r0_rd_out[53]
    DIRECTION OUTPUT ;
    USE SIGNAL ;
    SHAPE ABUTMENT ;
    PORT
      LAYER M3 ;
      RECT 217.611 0.000 217.629 0.054 ;
    END
  END r0_rd_out[53]
  PIN r0_rd_out[54]
    DIRECTION OUTPUT ;
    USE SIGNAL ;
    SHAPE ABUTMENT ;
    PORT
      LAYER M3 ;
      RECT 218.799 0.000 218.817 0.054 ;
    END
  END r0_rd_out[54]
  PIN r0_rd_out[55]
    DIRECTION OUTPUT ;
    USE SIGNAL ;
    SHAPE ABUTMENT ;
    PORT
      LAYER M3 ;
      RECT 219.987 0.000 220.005 0.054 ;
    END
  END r0_rd_out[55]
  PIN r0_rd_out[56]
    DIRECTION OUTPUT ;
    USE SIGNAL ;
    SHAPE ABUTMENT ;
    PORT
      LAYER M3 ;
      RECT 221.175 0.000 221.193 0.054 ;
    END
  END r0_rd_out[56]
  PIN r0_rd_out[57]
    DIRECTION OUTPUT ;
    USE SIGNAL ;
    SHAPE ABUTMENT ;
    PORT
      LAYER M3 ;
      RECT 222.363 0.000 222.381 0.054 ;
    END
  END r0_rd_out[57]
  PIN r0_rd_out[58]
    DIRECTION OUTPUT ;
    USE SIGNAL ;
    SHAPE ABUTMENT ;
    PORT
      LAYER M3 ;
      RECT 223.551 0.000 223.569 0.054 ;
    END
  END r0_rd_out[58]
  PIN r0_rd_out[59]
    DIRECTION OUTPUT ;
    USE SIGNAL ;
    SHAPE ABUTMENT ;
    PORT
      LAYER M3 ;
      RECT 224.739 0.000 224.757 0.054 ;
    END
  END r0_rd_out[59]
  PIN r0_rd_out[60]
    DIRECTION OUTPUT ;
    USE SIGNAL ;
    SHAPE ABUTMENT ;
    PORT
      LAYER M3 ;
      RECT 225.927 0.000 225.945 0.054 ;
    END
  END r0_rd_out[60]
  PIN r0_rd_out[61]
    DIRECTION OUTPUT ;
    USE SIGNAL ;
    SHAPE ABUTMENT ;
    PORT
      LAYER M3 ;
      RECT 227.115 0.000 227.133 0.054 ;
    END
  END r0_rd_out[61]
  PIN r0_rd_out[62]
    DIRECTION OUTPUT ;
    USE SIGNAL ;
    SHAPE ABUTMENT ;
    PORT
      LAYER M3 ;
      RECT 228.303 0.000 228.321 0.054 ;
    END
  END r0_rd_out[62]
  PIN r0_rd_out[63]
    DIRECTION OUTPUT ;
    USE SIGNAL ;
    SHAPE ABUTMENT ;
    PORT
      LAYER M3 ;
      RECT 229.491 0.000 229.509 0.054 ;
    END
  END r0_rd_out[63]
  PIN r0_rd_out[64]
    DIRECTION OUTPUT ;
    USE SIGNAL ;
    SHAPE ABUTMENT ;
    PORT
      LAYER M3 ;
      RECT 230.679 0.000 230.697 0.054 ;
    END
  END r0_rd_out[64]
  PIN r0_rd_out[65]
    DIRECTION OUTPUT ;
    USE SIGNAL ;
    SHAPE ABUTMENT ;
    PORT
      LAYER M3 ;
      RECT 114.867 293.707 114.885 293.761 ;
    END
  END r0_rd_out[65]
  PIN r0_rd_out[66]
    DIRECTION OUTPUT ;
    USE SIGNAL ;
    SHAPE ABUTMENT ;
    PORT
      LAYER M3 ;
      RECT 116.631 293.707 116.649 293.761 ;
    END
  END r0_rd_out[66]
  PIN r0_rd_out[67]
    DIRECTION OUTPUT ;
    USE SIGNAL ;
    SHAPE ABUTMENT ;
    PORT
      LAYER M3 ;
      RECT 118.395 293.707 118.413 293.761 ;
    END
  END r0_rd_out[67]
  PIN r0_rd_out[68]
    DIRECTION OUTPUT ;
    USE SIGNAL ;
    SHAPE ABUTMENT ;
    PORT
      LAYER M3 ;
      RECT 120.159 293.707 120.177 293.761 ;
    END
  END r0_rd_out[68]
  PIN r0_rd_out[69]
    DIRECTION OUTPUT ;
    USE SIGNAL ;
    SHAPE ABUTMENT ;
    PORT
      LAYER M3 ;
      RECT 121.923 293.707 121.941 293.761 ;
    END
  END r0_rd_out[69]
  PIN r0_rd_out[70]
    DIRECTION OUTPUT ;
    USE SIGNAL ;
    SHAPE ABUTMENT ;
    PORT
      LAYER M3 ;
      RECT 123.687 293.707 123.705 293.761 ;
    END
  END r0_rd_out[70]
  PIN r0_rd_out[71]
    DIRECTION OUTPUT ;
    USE SIGNAL ;
    SHAPE ABUTMENT ;
    PORT
      LAYER M3 ;
      RECT 125.451 293.707 125.469 293.761 ;
    END
  END r0_rd_out[71]
  PIN r0_rd_out[72]
    DIRECTION OUTPUT ;
    USE SIGNAL ;
    SHAPE ABUTMENT ;
    PORT
      LAYER M3 ;
      RECT 127.215 293.707 127.233 293.761 ;
    END
  END r0_rd_out[72]
  PIN r0_rd_out[73]
    DIRECTION OUTPUT ;
    USE SIGNAL ;
    SHAPE ABUTMENT ;
    PORT
      LAYER M3 ;
      RECT 128.979 293.707 128.997 293.761 ;
    END
  END r0_rd_out[73]
  PIN r0_rd_out[74]
    DIRECTION OUTPUT ;
    USE SIGNAL ;
    SHAPE ABUTMENT ;
    PORT
      LAYER M3 ;
      RECT 130.743 293.707 130.761 293.761 ;
    END
  END r0_rd_out[74]
  PIN r0_rd_out[75]
    DIRECTION OUTPUT ;
    USE SIGNAL ;
    SHAPE ABUTMENT ;
    PORT
      LAYER M3 ;
      RECT 132.507 293.707 132.525 293.761 ;
    END
  END r0_rd_out[75]
  PIN r0_rd_out[76]
    DIRECTION OUTPUT ;
    USE SIGNAL ;
    SHAPE ABUTMENT ;
    PORT
      LAYER M3 ;
      RECT 134.271 293.707 134.289 293.761 ;
    END
  END r0_rd_out[76]
  PIN r0_rd_out[77]
    DIRECTION OUTPUT ;
    USE SIGNAL ;
    SHAPE ABUTMENT ;
    PORT
      LAYER M3 ;
      RECT 136.035 293.707 136.053 293.761 ;
    END
  END r0_rd_out[77]
  PIN r0_rd_out[78]
    DIRECTION OUTPUT ;
    USE SIGNAL ;
    SHAPE ABUTMENT ;
    PORT
      LAYER M3 ;
      RECT 137.799 293.707 137.817 293.761 ;
    END
  END r0_rd_out[78]
  PIN r0_rd_out[79]
    DIRECTION OUTPUT ;
    USE SIGNAL ;
    SHAPE ABUTMENT ;
    PORT
      LAYER M3 ;
      RECT 139.563 293.707 139.581 293.761 ;
    END
  END r0_rd_out[79]
  PIN r0_rd_out[80]
    DIRECTION OUTPUT ;
    USE SIGNAL ;
    SHAPE ABUTMENT ;
    PORT
      LAYER M3 ;
      RECT 141.327 293.707 141.345 293.761 ;
    END
  END r0_rd_out[80]
  PIN r0_rd_out[81]
    DIRECTION OUTPUT ;
    USE SIGNAL ;
    SHAPE ABUTMENT ;
    PORT
      LAYER M3 ;
      RECT 143.091 293.707 143.109 293.761 ;
    END
  END r0_rd_out[81]
  PIN r0_rd_out[82]
    DIRECTION OUTPUT ;
    USE SIGNAL ;
    SHAPE ABUTMENT ;
    PORT
      LAYER M3 ;
      RECT 144.855 293.707 144.873 293.761 ;
    END
  END r0_rd_out[82]
  PIN r0_rd_out[83]
    DIRECTION OUTPUT ;
    USE SIGNAL ;
    SHAPE ABUTMENT ;
    PORT
      LAYER M3 ;
      RECT 146.619 293.707 146.637 293.761 ;
    END
  END r0_rd_out[83]
  PIN r0_rd_out[84]
    DIRECTION OUTPUT ;
    USE SIGNAL ;
    SHAPE ABUTMENT ;
    PORT
      LAYER M3 ;
      RECT 148.383 293.707 148.401 293.761 ;
    END
  END r0_rd_out[84]
  PIN r0_rd_out[85]
    DIRECTION OUTPUT ;
    USE SIGNAL ;
    SHAPE ABUTMENT ;
    PORT
      LAYER M3 ;
      RECT 150.147 293.707 150.165 293.761 ;
    END
  END r0_rd_out[85]
  PIN r0_rd_out[86]
    DIRECTION OUTPUT ;
    USE SIGNAL ;
    SHAPE ABUTMENT ;
    PORT
      LAYER M3 ;
      RECT 151.911 293.707 151.929 293.761 ;
    END
  END r0_rd_out[86]
  PIN r0_rd_out[87]
    DIRECTION OUTPUT ;
    USE SIGNAL ;
    SHAPE ABUTMENT ;
    PORT
      LAYER M3 ;
      RECT 153.675 293.707 153.693 293.761 ;
    END
  END r0_rd_out[87]
  PIN r0_rd_out[88]
    DIRECTION OUTPUT ;
    USE SIGNAL ;
    SHAPE ABUTMENT ;
    PORT
      LAYER M3 ;
      RECT 155.439 293.707 155.457 293.761 ;
    END
  END r0_rd_out[88]
  PIN r0_rd_out[89]
    DIRECTION OUTPUT ;
    USE SIGNAL ;
    SHAPE ABUTMENT ;
    PORT
      LAYER M3 ;
      RECT 157.203 293.707 157.221 293.761 ;
    END
  END r0_rd_out[89]
  PIN r0_rd_out[90]
    DIRECTION OUTPUT ;
    USE SIGNAL ;
    SHAPE ABUTMENT ;
    PORT
      LAYER M3 ;
      RECT 158.967 293.707 158.985 293.761 ;
    END
  END r0_rd_out[90]
  PIN r0_rd_out[91]
    DIRECTION OUTPUT ;
    USE SIGNAL ;
    SHAPE ABUTMENT ;
    PORT
      LAYER M3 ;
      RECT 160.731 293.707 160.749 293.761 ;
    END
  END r0_rd_out[91]
  PIN r0_rd_out[92]
    DIRECTION OUTPUT ;
    USE SIGNAL ;
    SHAPE ABUTMENT ;
    PORT
      LAYER M3 ;
      RECT 162.495 293.707 162.513 293.761 ;
    END
  END r0_rd_out[92]
  PIN r0_rd_out[93]
    DIRECTION OUTPUT ;
    USE SIGNAL ;
    SHAPE ABUTMENT ;
    PORT
      LAYER M3 ;
      RECT 164.259 293.707 164.277 293.761 ;
    END
  END r0_rd_out[93]
  PIN r0_rd_out[94]
    DIRECTION OUTPUT ;
    USE SIGNAL ;
    SHAPE ABUTMENT ;
    PORT
      LAYER M3 ;
      RECT 166.023 293.707 166.041 293.761 ;
    END
  END r0_rd_out[94]
  PIN r0_rd_out[95]
    DIRECTION OUTPUT ;
    USE SIGNAL ;
    SHAPE ABUTMENT ;
    PORT
      LAYER M3 ;
      RECT 167.787 293.707 167.805 293.761 ;
    END
  END r0_rd_out[95]
  PIN r0_rd_out[96]
    DIRECTION OUTPUT ;
    USE SIGNAL ;
    SHAPE ABUTMENT ;
    PORT
      LAYER M3 ;
      RECT 169.551 293.707 169.569 293.761 ;
    END
  END r0_rd_out[96]
  PIN r0_rd_out[97]
    DIRECTION OUTPUT ;
    USE SIGNAL ;
    SHAPE ABUTMENT ;
    PORT
      LAYER M3 ;
      RECT 171.315 293.707 171.333 293.761 ;
    END
  END r0_rd_out[97]
  PIN r0_rd_out[98]
    DIRECTION OUTPUT ;
    USE SIGNAL ;
    SHAPE ABUTMENT ;
    PORT
      LAYER M3 ;
      RECT 173.079 293.707 173.097 293.761 ;
    END
  END r0_rd_out[98]
  PIN r0_rd_out[99]
    DIRECTION OUTPUT ;
    USE SIGNAL ;
    SHAPE ABUTMENT ;
    PORT
      LAYER M3 ;
      RECT 174.843 293.707 174.861 293.761 ;
    END
  END r0_rd_out[99]
  PIN r0_rd_out[100]
    DIRECTION OUTPUT ;
    USE SIGNAL ;
    SHAPE ABUTMENT ;
    PORT
      LAYER M3 ;
      RECT 176.607 293.707 176.625 293.761 ;
    END
  END r0_rd_out[100]
  PIN r0_rd_out[101]
    DIRECTION OUTPUT ;
    USE SIGNAL ;
    SHAPE ABUTMENT ;
    PORT
      LAYER M3 ;
      RECT 178.371 293.707 178.389 293.761 ;
    END
  END r0_rd_out[101]
  PIN r0_rd_out[102]
    DIRECTION OUTPUT ;
    USE SIGNAL ;
    SHAPE ABUTMENT ;
    PORT
      LAYER M3 ;
      RECT 180.135 293.707 180.153 293.761 ;
    END
  END r0_rd_out[102]
  PIN r0_rd_out[103]
    DIRECTION OUTPUT ;
    USE SIGNAL ;
    SHAPE ABUTMENT ;
    PORT
      LAYER M3 ;
      RECT 181.899 293.707 181.917 293.761 ;
    END
  END r0_rd_out[103]
  PIN r0_rd_out[104]
    DIRECTION OUTPUT ;
    USE SIGNAL ;
    SHAPE ABUTMENT ;
    PORT
      LAYER M3 ;
      RECT 183.663 293.707 183.681 293.761 ;
    END
  END r0_rd_out[104]
  PIN r0_rd_out[105]
    DIRECTION OUTPUT ;
    USE SIGNAL ;
    SHAPE ABUTMENT ;
    PORT
      LAYER M3 ;
      RECT 185.427 293.707 185.445 293.761 ;
    END
  END r0_rd_out[105]
  PIN r0_rd_out[106]
    DIRECTION OUTPUT ;
    USE SIGNAL ;
    SHAPE ABUTMENT ;
    PORT
      LAYER M3 ;
      RECT 187.191 293.707 187.209 293.761 ;
    END
  END r0_rd_out[106]
  PIN r0_rd_out[107]
    DIRECTION OUTPUT ;
    USE SIGNAL ;
    SHAPE ABUTMENT ;
    PORT
      LAYER M3 ;
      RECT 188.955 293.707 188.973 293.761 ;
    END
  END r0_rd_out[107]
  PIN r0_rd_out[108]
    DIRECTION OUTPUT ;
    USE SIGNAL ;
    SHAPE ABUTMENT ;
    PORT
      LAYER M3 ;
      RECT 190.719 293.707 190.737 293.761 ;
    END
  END r0_rd_out[108]
  PIN r0_rd_out[109]
    DIRECTION OUTPUT ;
    USE SIGNAL ;
    SHAPE ABUTMENT ;
    PORT
      LAYER M3 ;
      RECT 192.483 293.707 192.501 293.761 ;
    END
  END r0_rd_out[109]
  PIN r0_rd_out[110]
    DIRECTION OUTPUT ;
    USE SIGNAL ;
    SHAPE ABUTMENT ;
    PORT
      LAYER M3 ;
      RECT 194.247 293.707 194.265 293.761 ;
    END
  END r0_rd_out[110]
  PIN r0_rd_out[111]
    DIRECTION OUTPUT ;
    USE SIGNAL ;
    SHAPE ABUTMENT ;
    PORT
      LAYER M3 ;
      RECT 196.011 293.707 196.029 293.761 ;
    END
  END r0_rd_out[111]
  PIN r0_rd_out[112]
    DIRECTION OUTPUT ;
    USE SIGNAL ;
    SHAPE ABUTMENT ;
    PORT
      LAYER M3 ;
      RECT 197.775 293.707 197.793 293.761 ;
    END
  END r0_rd_out[112]
  PIN r0_rd_out[113]
    DIRECTION OUTPUT ;
    USE SIGNAL ;
    SHAPE ABUTMENT ;
    PORT
      LAYER M3 ;
      RECT 199.539 293.707 199.557 293.761 ;
    END
  END r0_rd_out[113]
  PIN r0_rd_out[114]
    DIRECTION OUTPUT ;
    USE SIGNAL ;
    SHAPE ABUTMENT ;
    PORT
      LAYER M3 ;
      RECT 201.303 293.707 201.321 293.761 ;
    END
  END r0_rd_out[114]
  PIN r0_rd_out[115]
    DIRECTION OUTPUT ;
    USE SIGNAL ;
    SHAPE ABUTMENT ;
    PORT
      LAYER M3 ;
      RECT 203.067 293.707 203.085 293.761 ;
    END
  END r0_rd_out[115]
  PIN r0_rd_out[116]
    DIRECTION OUTPUT ;
    USE SIGNAL ;
    SHAPE ABUTMENT ;
    PORT
      LAYER M3 ;
      RECT 204.831 293.707 204.849 293.761 ;
    END
  END r0_rd_out[116]
  PIN r0_rd_out[117]
    DIRECTION OUTPUT ;
    USE SIGNAL ;
    SHAPE ABUTMENT ;
    PORT
      LAYER M3 ;
      RECT 206.595 293.707 206.613 293.761 ;
    END
  END r0_rd_out[117]
  PIN r0_rd_out[118]
    DIRECTION OUTPUT ;
    USE SIGNAL ;
    SHAPE ABUTMENT ;
    PORT
      LAYER M3 ;
      RECT 208.359 293.707 208.377 293.761 ;
    END
  END r0_rd_out[118]
  PIN r0_rd_out[119]
    DIRECTION OUTPUT ;
    USE SIGNAL ;
    SHAPE ABUTMENT ;
    PORT
      LAYER M3 ;
      RECT 210.123 293.707 210.141 293.761 ;
    END
  END r0_rd_out[119]
  PIN r0_rd_out[120]
    DIRECTION OUTPUT ;
    USE SIGNAL ;
    SHAPE ABUTMENT ;
    PORT
      LAYER M3 ;
      RECT 211.887 293.707 211.905 293.761 ;
    END
  END r0_rd_out[120]
  PIN r0_rd_out[121]
    DIRECTION OUTPUT ;
    USE SIGNAL ;
    SHAPE ABUTMENT ;
    PORT
      LAYER M3 ;
      RECT 213.651 293.707 213.669 293.761 ;
    END
  END r0_rd_out[121]
  PIN r0_rd_out[122]
    DIRECTION OUTPUT ;
    USE SIGNAL ;
    SHAPE ABUTMENT ;
    PORT
      LAYER M3 ;
      RECT 215.415 293.707 215.433 293.761 ;
    END
  END r0_rd_out[122]
  PIN r0_rd_out[123]
    DIRECTION OUTPUT ;
    USE SIGNAL ;
    SHAPE ABUTMENT ;
    PORT
      LAYER M3 ;
      RECT 217.179 293.707 217.197 293.761 ;
    END
  END r0_rd_out[123]
  PIN r0_rd_out[124]
    DIRECTION OUTPUT ;
    USE SIGNAL ;
    SHAPE ABUTMENT ;
    PORT
      LAYER M3 ;
      RECT 218.943 293.707 218.961 293.761 ;
    END
  END r0_rd_out[124]
  PIN r0_rd_out[125]
    DIRECTION OUTPUT ;
    USE SIGNAL ;
    SHAPE ABUTMENT ;
    PORT
      LAYER M3 ;
      RECT 220.707 293.707 220.725 293.761 ;
    END
  END r0_rd_out[125]
  PIN r0_rd_out[126]
    DIRECTION OUTPUT ;
    USE SIGNAL ;
    SHAPE ABUTMENT ;
    PORT
      LAYER M3 ;
      RECT 222.471 293.707 222.489 293.761 ;
    END
  END r0_rd_out[126]
  PIN r0_rd_out[127]
    DIRECTION OUTPUT ;
    USE SIGNAL ;
    SHAPE ABUTMENT ;
    PORT
      LAYER M3 ;
      RECT 224.235 293.707 224.253 293.761 ;
    END
  END r0_rd_out[127]
  PIN r0_rd_out[128]
    DIRECTION OUTPUT ;
    USE SIGNAL ;
    SHAPE ABUTMENT ;
    PORT
      LAYER M3 ;
      RECT 225.999 293.707 226.017 293.761 ;
    END
  END r0_rd_out[128]
  PIN r0_rd_out[129]
    DIRECTION OUTPUT ;
    USE SIGNAL ;
    SHAPE ABUTMENT ;
    PORT
      LAYER M3 ;
      RECT 227.763 293.707 227.781 293.761 ;
    END
  END r0_rd_out[129]
  PIN rw0_addr_in[0]
    DIRECTION INPUT ;
    USE SIGNAL ;
    SHAPE ABUTMENT ;
    PORT
      LAYER M4 ;
      RECT 0.000 225.204 0.072 225.228 ;
    END
  END rw0_addr_in[0]
  PIN rw0_addr_in[1]
    DIRECTION INPUT ;
    USE SIGNAL ;
    SHAPE ABUTMENT ;
    PORT
      LAYER M4 ;
      RECT 0.000 232.020 0.072 232.044 ;
    END
  END rw0_addr_in[1]
  PIN rw0_addr_in[2]
    DIRECTION INPUT ;
    USE SIGNAL ;
    SHAPE ABUTMENT ;
    PORT
      LAYER M4 ;
      RECT 0.000 238.836 0.072 238.860 ;
    END
  END rw0_addr_in[2]
  PIN rw0_addr_in[3]
    DIRECTION INPUT ;
    USE SIGNAL ;
    SHAPE ABUTMENT ;
    PORT
      LAYER M4 ;
      RECT 0.000 245.652 0.072 245.676 ;
    END
  END rw0_addr_in[3]
  PIN rw0_addr_in[4]
    DIRECTION INPUT ;
    USE SIGNAL ;
    SHAPE ABUTMENT ;
    PORT
      LAYER M4 ;
      RECT 0.000 252.468 0.072 252.492 ;
    END
  END rw0_addr_in[4]
  PIN rw0_addr_in[5]
    DIRECTION INPUT ;
    USE SIGNAL ;
    SHAPE ABUTMENT ;
    PORT
      LAYER M4 ;
      RECT 238.608 218.388 238.680 218.412 ;
    END
  END rw0_addr_in[5]
  PIN rw0_addr_in[6]
    DIRECTION INPUT ;
    USE SIGNAL ;
    SHAPE ABUTMENT ;
    PORT
      LAYER M4 ;
      RECT 238.608 225.204 238.680 225.228 ;
    END
  END rw0_addr_in[6]
  PIN rw0_addr_in[7]
    DIRECTION INPUT ;
    USE SIGNAL ;
    SHAPE ABUTMENT ;
    PORT
      LAYER M4 ;
      RECT 238.608 232.020 238.680 232.044 ;
    END
  END rw0_addr_in[7]
  PIN rw0_addr_in[8]
    DIRECTION INPUT ;
    USE SIGNAL ;
    SHAPE ABUTMENT ;
    PORT
      LAYER M4 ;
      RECT 238.608 238.836 238.680 238.860 ;
    END
  END rw0_addr_in[8]
  PIN rw0_addr_in[9]
    DIRECTION INPUT ;
    USE SIGNAL ;
    SHAPE ABUTMENT ;
    PORT
      LAYER M4 ;
      RECT 238.608 245.652 238.680 245.676 ;
    END
  END rw0_addr_in[9]
  PIN r0_addr_in[0]
    DIRECTION INPUT ;
    USE SIGNAL ;
    SHAPE ABUTMENT ;
    PORT
      LAYER M4 ;
      RECT 0.000 259.284 0.072 259.308 ;
    END
  END r0_addr_in[0]
  PIN r0_addr_in[1]
    DIRECTION INPUT ;
    USE SIGNAL ;
    SHAPE ABUTMENT ;
    PORT
      LAYER M4 ;
      RECT 0.000 266.100 0.072 266.124 ;
    END
  END r0_addr_in[1]
  PIN r0_addr_in[2]
    DIRECTION INPUT ;
    USE SIGNAL ;
    SHAPE ABUTMENT ;
    PORT
      LAYER M4 ;
      RECT 0.000 272.916 0.072 272.940 ;
    END
  END r0_addr_in[2]
  PIN r0_addr_in[3]
    DIRECTION INPUT ;
    USE SIGNAL ;
    SHAPE ABUTMENT ;
    PORT
      LAYER M4 ;
      RECT 0.000 279.732 0.072 279.756 ;
    END
  END r0_addr_in[3]
  PIN r0_addr_in[4]
    DIRECTION INPUT ;
    USE SIGNAL ;
    SHAPE ABUTMENT ;
    PORT
      LAYER M4 ;
      RECT 0.000 286.548 0.072 286.572 ;
    END
  END r0_addr_in[4]
  PIN r0_addr_in[5]
    DIRECTION INPUT ;
    USE SIGNAL ;
    SHAPE ABUTMENT ;
    PORT
      LAYER M4 ;
      RECT 238.608 252.468 238.680 252.492 ;
    END
  END r0_addr_in[5]
  PIN r0_addr_in[6]
    DIRECTION INPUT ;
    USE SIGNAL ;
    SHAPE ABUTMENT ;
    PORT
      LAYER M4 ;
      RECT 238.608 259.284 238.680 259.308 ;
    END
  END r0_addr_in[6]
  PIN r0_addr_in[7]
    DIRECTION INPUT ;
    USE SIGNAL ;
    SHAPE ABUTMENT ;
    PORT
      LAYER M4 ;
      RECT 238.608 266.100 238.680 266.124 ;
    END
  END r0_addr_in[7]
  PIN r0_addr_in[8]
    DIRECTION INPUT ;
    USE SIGNAL ;
    SHAPE ABUTMENT ;
    PORT
      LAYER M4 ;
      RECT 238.608 272.916 238.680 272.940 ;
    END
  END r0_addr_in[8]
  PIN r0_addr_in[9]
    DIRECTION INPUT ;
    USE SIGNAL ;
    SHAPE ABUTMENT ;
    PORT
      LAYER M4 ;
      RECT 238.608 279.732 238.680 279.756 ;
    END
  END r0_addr_in[9]
  PIN rw0_we_in
    DIRECTION INPUT ;
    USE SIGNAL ;
    SHAPE ABUTMENT ;
    PORT
      LAYER M3 ;
      RECT 229.527 293.707 229.545 293.761 ;
    END
  END rw0_we_in
  PIN rw0_ce_in
    DIRECTION INPUT ;
    USE SIGNAL ;
    SHAPE ABUTMENT ;
    PORT
      LAYER M3 ;
      RECT 231.291 293.707 231.309 293.761 ;
    END
  END rw0_ce_in
  PIN rw0_clk
    DIRECTION INPUT ;
    USE SIGNAL ;
    SHAPE ABUTMENT ;
    PORT
      LAYER M3 ;
      RECT 233.055 293.707 233.073 293.761 ;
    END
  END rw0_clk
  PIN r0_ce_in
    DIRECTION INPUT ;
    USE SIGNAL ;
    SHAPE ABUTMENT ;
    PORT
      LAYER M3 ;
      RECT 234.819 293.707 234.837 293.761 ;
    END
  END r0_ce_in
  PIN r0_clk
    DIRECTION INPUT ;
    USE SIGNAL ;
    SHAPE ABUTMENT ;
    PORT
      LAYER M3 ;
      RECT 236.583 293.707 236.601 293.761 ;
    END
  END r0_clk
  PIN VSS
    DIRECTION INOUT ;
    USE GROUND ;
    PORT
      LAYER M4 ;
      RECT 0.216 0.240 238.464 0.336 ;
      RECT 0.216 1.008 238.464 1.104 ;
      RECT 0.216 1.776 238.464 1.872 ;
      RECT 0.216 2.544 238.464 2.640 ;
      RECT 0.216 3.312 238.464 3.408 ;
      RECT 0.216 4.080 238.464 4.176 ;
      RECT 0.216 4.848 238.464 4.944 ;
      RECT 0.216 5.616 238.464 5.712 ;
      RECT 0.216 6.384 238.464 6.480 ;
      RECT 0.216 7.152 238.464 7.248 ;
      RECT 0.216 7.920 238.464 8.016 ;
      RECT 0.216 8.688 238.464 8.784 ;
      RECT 0.216 9.456 238.464 9.552 ;
      RECT 0.216 10.224 238.464 10.320 ;
      RECT 0.216 10.992 238.464 11.088 ;
      RECT 0.216 11.760 238.464 11.856 ;
      RECT 0.216 12.528 238.464 12.624 ;
      RECT 0.216 13.296 238.464 13.392 ;
      RECT 0.216 14.064 238.464 14.160 ;
      RECT 0.216 14.832 238.464 14.928 ;
      RECT 0.216 15.600 238.464 15.696 ;
      RECT 0.216 16.368 238.464 16.464 ;
      RECT 0.216 17.136 238.464 17.232 ;
      RECT 0.216 17.904 238.464 18.000 ;
      RECT 0.216 18.672 238.464 18.768 ;
      RECT 0.216 19.440 238.464 19.536 ;
      RECT 0.216 20.208 238.464 20.304 ;
      RECT 0.216 20.976 238.464 21.072 ;
      RECT 0.216 21.744 238.464 21.840 ;
      RECT 0.216 22.512 238.464 22.608 ;
      RECT 0.216 23.280 238.464 23.376 ;
      RECT 0.216 24.048 238.464 24.144 ;
      RECT 0.216 24.816 238.464 24.912 ;
      RECT 0.216 25.584 238.464 25.680 ;
      RECT 0.216 26.352 238.464 26.448 ;
      RECT 0.216 27.120 238.464 27.216 ;
      RECT 0.216 27.888 238.464 27.984 ;
      RECT 0.216 28.656 238.464 28.752 ;
      RECT 0.216 29.424 238.464 29.520 ;
      RECT 0.216 30.192 238.464 30.288 ;
      RECT 0.216 30.960 238.464 31.056 ;
      RECT 0.216 31.728 238.464 31.824 ;
      RECT 0.216 32.496 238.464 32.592 ;
      RECT 0.216 33.264 238.464 33.360 ;
      RECT 0.216 34.032 238.464 34.128 ;
      RECT 0.216 34.800 238.464 34.896 ;
      RECT 0.216 35.568 238.464 35.664 ;
      RECT 0.216 36.336 238.464 36.432 ;
      RECT 0.216 37.104 238.464 37.200 ;
      RECT 0.216 37.872 238.464 37.968 ;
      RECT 0.216 38.640 238.464 38.736 ;
      RECT 0.216 39.408 238.464 39.504 ;
      RECT 0.216 40.176 238.464 40.272 ;
      RECT 0.216 40.944 238.464 41.040 ;
      RECT 0.216 41.712 238.464 41.808 ;
      RECT 0.216 42.480 238.464 42.576 ;
      RECT 0.216 43.248 238.464 43.344 ;
      RECT 0.216 44.016 238.464 44.112 ;
      RECT 0.216 44.784 238.464 44.880 ;
      RECT 0.216 45.552 238.464 45.648 ;
      RECT 0.216 46.320 238.464 46.416 ;
      RECT 0.216 47.088 238.464 47.184 ;
      RECT 0.216 47.856 238.464 47.952 ;
      RECT 0.216 48.624 238.464 48.720 ;
      RECT 0.216 49.392 238.464 49.488 ;
      RECT 0.216 50.160 238.464 50.256 ;
      RECT 0.216 50.928 238.464 51.024 ;
      RECT 0.216 51.696 238.464 51.792 ;
      RECT 0.216 52.464 238.464 52.560 ;
      RECT 0.216 53.232 238.464 53.328 ;
      RECT 0.216 54.000 238.464 54.096 ;
      RECT 0.216 54.768 238.464 54.864 ;
      RECT 0.216 55.536 238.464 55.632 ;
      RECT 0.216 56.304 238.464 56.400 ;
      RECT 0.216 57.072 238.464 57.168 ;
      RECT 0.216 57.840 238.464 57.936 ;
      RECT 0.216 58.608 238.464 58.704 ;
      RECT 0.216 59.376 238.464 59.472 ;
      RECT 0.216 60.144 238.464 60.240 ;
      RECT 0.216 60.912 238.464 61.008 ;
      RECT 0.216 61.680 238.464 61.776 ;
      RECT 0.216 62.448 238.464 62.544 ;
      RECT 0.216 63.216 238.464 63.312 ;
      RECT 0.216 63.984 238.464 64.080 ;
      RECT 0.216 64.752 238.464 64.848 ;
      RECT 0.216 65.520 238.464 65.616 ;
      RECT 0.216 66.288 238.464 66.384 ;
      RECT 0.216 67.056 238.464 67.152 ;
      RECT 0.216 67.824 238.464 67.920 ;
      RECT 0.216 68.592 238.464 68.688 ;
      RECT 0.216 69.360 238.464 69.456 ;
      RECT 0.216 70.128 238.464 70.224 ;
      RECT 0.216 70.896 238.464 70.992 ;
      RECT 0.216 71.664 238.464 71.760 ;
      RECT 0.216 72.432 238.464 72.528 ;
      RECT 0.216 73.200 238.464 73.296 ;
      RECT 0.216 73.968 238.464 74.064 ;
      RECT 0.216 74.736 238.464 74.832 ;
      RECT 0.216 75.504 238.464 75.600 ;
      RECT 0.216 76.272 238.464 76.368 ;
      RECT 0.216 77.040 238.464 77.136 ;
      RECT 0.216 77.808 238.464 77.904 ;
      RECT 0.216 78.576 238.464 78.672 ;
      RECT 0.216 79.344 238.464 79.440 ;
      RECT 0.216 80.112 238.464 80.208 ;
      RECT 0.216 80.880 238.464 80.976 ;
      RECT 0.216 81.648 238.464 81.744 ;
      RECT 0.216 82.416 238.464 82.512 ;
      RECT 0.216 83.184 238.464 83.280 ;
      RECT 0.216 83.952 238.464 84.048 ;
      RECT 0.216 84.720 238.464 84.816 ;
      RECT 0.216 85.488 238.464 85.584 ;
      RECT 0.216 86.256 238.464 86.352 ;
      RECT 0.216 87.024 238.464 87.120 ;
      RECT 0.216 87.792 238.464 87.888 ;
      RECT 0.216 88.560 238.464 88.656 ;
      RECT 0.216 89.328 238.464 89.424 ;
      RECT 0.216 90.096 238.464 90.192 ;
      RECT 0.216 90.864 238.464 90.960 ;
      RECT 0.216 91.632 238.464 91.728 ;
      RECT 0.216 92.400 238.464 92.496 ;
      RECT 0.216 93.168 238.464 93.264 ;
      RECT 0.216 93.936 238.464 94.032 ;
      RECT 0.216 94.704 238.464 94.800 ;
      RECT 0.216 95.472 238.464 95.568 ;
      RECT 0.216 96.240 238.464 96.336 ;
      RECT 0.216 97.008 238.464 97.104 ;
      RECT 0.216 97.776 238.464 97.872 ;
      RECT 0.216 98.544 238.464 98.640 ;
      RECT 0.216 99.312 238.464 99.408 ;
      RECT 0.216 100.080 238.464 100.176 ;
      RECT 0.216 100.848 238.464 100.944 ;
      RECT 0.216 101.616 238.464 101.712 ;
      RECT 0.216 102.384 238.464 102.480 ;
      RECT 0.216 103.152 238.464 103.248 ;
      RECT 0.216 103.920 238.464 104.016 ;
      RECT 0.216 104.688 238.464 104.784 ;
      RECT 0.216 105.456 238.464 105.552 ;
      RECT 0.216 106.224 238.464 106.320 ;
      RECT 0.216 106.992 238.464 107.088 ;
      RECT 0.216 107.760 238.464 107.856 ;
      RECT 0.216 108.528 238.464 108.624 ;
      RECT 0.216 109.296 238.464 109.392 ;
      RECT 0.216 110.064 238.464 110.160 ;
      RECT 0.216 110.832 238.464 110.928 ;
      RECT 0.216 111.600 238.464 111.696 ;
      RECT 0.216 112.368 238.464 112.464 ;
      RECT 0.216 113.136 238.464 113.232 ;
      RECT 0.216 113.904 238.464 114.000 ;
      RECT 0.216 114.672 238.464 114.768 ;
      RECT 0.216 115.440 238.464 115.536 ;
      RECT 0.216 116.208 238.464 116.304 ;
      RECT 0.216 116.976 238.464 117.072 ;
      RECT 0.216 117.744 238.464 117.840 ;
      RECT 0.216 118.512 238.464 118.608 ;
      RECT 0.216 119.280 238.464 119.376 ;
      RECT 0.216 120.048 238.464 120.144 ;
      RECT 0.216 120.816 238.464 120.912 ;
      RECT 0.216 121.584 238.464 121.680 ;
      RECT 0.216 122.352 238.464 122.448 ;
      RECT 0.216 123.120 238.464 123.216 ;
      RECT 0.216 123.888 238.464 123.984 ;
      RECT 0.216 124.656 238.464 124.752 ;
      RECT 0.216 125.424 238.464 125.520 ;
      RECT 0.216 126.192 238.464 126.288 ;
      RECT 0.216 126.960 238.464 127.056 ;
      RECT 0.216 127.728 238.464 127.824 ;
      RECT 0.216 128.496 238.464 128.592 ;
      RECT 0.216 129.264 238.464 129.360 ;
      RECT 0.216 130.032 238.464 130.128 ;
      RECT 0.216 130.800 238.464 130.896 ;
      RECT 0.216 131.568 238.464 131.664 ;
      RECT 0.216 132.336 238.464 132.432 ;
      RECT 0.216 133.104 238.464 133.200 ;
      RECT 0.216 133.872 238.464 133.968 ;
      RECT 0.216 134.640 238.464 134.736 ;
      RECT 0.216 135.408 238.464 135.504 ;
      RECT 0.216 136.176 238.464 136.272 ;
      RECT 0.216 136.944 238.464 137.040 ;
      RECT 0.216 137.712 238.464 137.808 ;
      RECT 0.216 138.480 238.464 138.576 ;
      RECT 0.216 139.248 238.464 139.344 ;
      RECT 0.216 140.016 238.464 140.112 ;
      RECT 0.216 140.784 238.464 140.880 ;
      RECT 0.216 141.552 238.464 141.648 ;
      RECT 0.216 142.320 238.464 142.416 ;
      RECT 0.216 143.088 238.464 143.184 ;
      RECT 0.216 143.856 238.464 143.952 ;
      RECT 0.216 144.624 238.464 144.720 ;
      RECT 0.216 145.392 238.464 145.488 ;
      RECT 0.216 146.160 238.464 146.256 ;
      RECT 0.216 146.928 238.464 147.024 ;
      RECT 0.216 147.696 238.464 147.792 ;
      RECT 0.216 148.464 238.464 148.560 ;
      RECT 0.216 149.232 238.464 149.328 ;
      RECT 0.216 150.000 238.464 150.096 ;
      RECT 0.216 150.768 238.464 150.864 ;
      RECT 0.216 151.536 238.464 151.632 ;
      RECT 0.216 152.304 238.464 152.400 ;
      RECT 0.216 153.072 238.464 153.168 ;
      RECT 0.216 153.840 238.464 153.936 ;
      RECT 0.216 154.608 238.464 154.704 ;
      RECT 0.216 155.376 238.464 155.472 ;
      RECT 0.216 156.144 238.464 156.240 ;
      RECT 0.216 156.912 238.464 157.008 ;
      RECT 0.216 157.680 238.464 157.776 ;
      RECT 0.216 158.448 238.464 158.544 ;
      RECT 0.216 159.216 238.464 159.312 ;
      RECT 0.216 159.984 238.464 160.080 ;
      RECT 0.216 160.752 238.464 160.848 ;
      RECT 0.216 161.520 238.464 161.616 ;
      RECT 0.216 162.288 238.464 162.384 ;
      RECT 0.216 163.056 238.464 163.152 ;
      RECT 0.216 163.824 238.464 163.920 ;
      RECT 0.216 164.592 238.464 164.688 ;
      RECT 0.216 165.360 238.464 165.456 ;
      RECT 0.216 166.128 238.464 166.224 ;
      RECT 0.216 166.896 238.464 166.992 ;
      RECT 0.216 167.664 238.464 167.760 ;
      RECT 0.216 168.432 238.464 168.528 ;
      RECT 0.216 169.200 238.464 169.296 ;
      RECT 0.216 169.968 238.464 170.064 ;
      RECT 0.216 170.736 238.464 170.832 ;
      RECT 0.216 171.504 238.464 171.600 ;
      RECT 0.216 172.272 238.464 172.368 ;
      RECT 0.216 173.040 238.464 173.136 ;
      RECT 0.216 173.808 238.464 173.904 ;
      RECT 0.216 174.576 238.464 174.672 ;
      RECT 0.216 175.344 238.464 175.440 ;
      RECT 0.216 176.112 238.464 176.208 ;
      RECT 0.216 176.880 238.464 176.976 ;
      RECT 0.216 177.648 238.464 177.744 ;
      RECT 0.216 178.416 238.464 178.512 ;
      RECT 0.216 179.184 238.464 179.280 ;
      RECT 0.216 179.952 238.464 180.048 ;
      RECT 0.216 180.720 238.464 180.816 ;
      RECT 0.216 181.488 238.464 181.584 ;
      RECT 0.216 182.256 238.464 182.352 ;
      RECT 0.216 183.024 238.464 183.120 ;
      RECT 0.216 183.792 238.464 183.888 ;
      RECT 0.216 184.560 238.464 184.656 ;
      RECT 0.216 185.328 238.464 185.424 ;
      RECT 0.216 186.096 238.464 186.192 ;
      RECT 0.216 186.864 238.464 186.960 ;
      RECT 0.216 187.632 238.464 187.728 ;
      RECT 0.216 188.400 238.464 188.496 ;
      RECT 0.216 189.168 238.464 189.264 ;
      RECT 0.216 189.936 238.464 190.032 ;
      RECT 0.216 190.704 238.464 190.800 ;
      RECT 0.216 191.472 238.464 191.568 ;
      RECT 0.216 192.240 238.464 192.336 ;
      RECT 0.216 193.008 238.464 193.104 ;
      RECT 0.216 193.776 238.464 193.872 ;
      RECT 0.216 194.544 238.464 194.640 ;
      RECT 0.216 195.312 238.464 195.408 ;
      RECT 0.216 196.080 238.464 196.176 ;
      RECT 0.216 196.848 238.464 196.944 ;
      RECT 0.216 197.616 238.464 197.712 ;
      RECT 0.216 198.384 238.464 198.480 ;
      RECT 0.216 199.152 238.464 199.248 ;
      RECT 0.216 199.920 238.464 200.016 ;
      RECT 0.216 200.688 238.464 200.784 ;
      RECT 0.216 201.456 238.464 201.552 ;
      RECT 0.216 202.224 238.464 202.320 ;
      RECT 0.216 202.992 238.464 203.088 ;
      RECT 0.216 203.760 238.464 203.856 ;
      RECT 0.216 204.528 238.464 204.624 ;
      RECT 0.216 205.296 238.464 205.392 ;
      RECT 0.216 206.064 238.464 206.160 ;
      RECT 0.216 206.832 238.464 206.928 ;
      RECT 0.216 207.600 238.464 207.696 ;
      RECT 0.216 208.368 238.464 208.464 ;
      RECT 0.216 209.136 238.464 209.232 ;
      RECT 0.216 209.904 238.464 210.000 ;
      RECT 0.216 210.672 238.464 210.768 ;
      RECT 0.216 211.440 238.464 211.536 ;
      RECT 0.216 212.208 238.464 212.304 ;
      RECT 0.216 212.976 238.464 213.072 ;
      RECT 0.216 213.744 238.464 213.840 ;
      RECT 0.216 214.512 238.464 214.608 ;
      RECT 0.216 215.280 238.464 215.376 ;
      RECT 0.216 216.048 238.464 216.144 ;
      RECT 0.216 216.816 238.464 216.912 ;
      RECT 0.216 217.584 238.464 217.680 ;
      RECT 0.216 218.352 238.464 218.448 ;
      RECT 0.216 219.120 238.464 219.216 ;
      RECT 0.216 219.888 238.464 219.984 ;
      RECT 0.216 220.656 238.464 220.752 ;
      RECT 0.216 221.424 238.464 221.520 ;
      RECT 0.216 222.192 238.464 222.288 ;
      RECT 0.216 222.960 238.464 223.056 ;
      RECT 0.216 223.728 238.464 223.824 ;
      RECT 0.216 224.496 238.464 224.592 ;
      RECT 0.216 225.264 238.464 225.360 ;
      RECT 0.216 226.032 238.464 226.128 ;
      RECT 0.216 226.800 238.464 226.896 ;
      RECT 0.216 227.568 238.464 227.664 ;
      RECT 0.216 228.336 238.464 228.432 ;
      RECT 0.216 229.104 238.464 229.200 ;
      RECT 0.216 229.872 238.464 229.968 ;
      RECT 0.216 230.640 238.464 230.736 ;
      RECT 0.216 231.408 238.464 231.504 ;
      RECT 0.216 232.176 238.464 232.272 ;
      RECT 0.216 232.944 238.464 233.040 ;
      RECT 0.216 233.712 238.464 233.808 ;
      RECT 0.216 234.480 238.464 234.576 ;
      RECT 0.216 235.248 238.464 235.344 ;
      RECT 0.216 236.016 238.464 236.112 ;
      RECT 0.216 236.784 238.464 236.880 ;
      RECT 0.216 237.552 238.464 237.648 ;
      RECT 0.216 238.320 238.464 238.416 ;
      RECT 0.216 239.088 238.464 239.184 ;
      RECT 0.216 239.856 238.464 239.952 ;
      RECT 0.216 240.624 238.464 240.720 ;
      RECT 0.216 241.392 238.464 241.488 ;
      RECT 0.216 242.160 238.464 242.256 ;
      RECT 0.216 242.928 238.464 243.024 ;
      RECT 0.216 243.696 238.464 243.792 ;
      RECT 0.216 244.464 238.464 244.560 ;
      RECT 0.216 245.232 238.464 245.328 ;
      RECT 0.216 246.000 238.464 246.096 ;
      RECT 0.216 246.768 238.464 246.864 ;
      RECT 0.216 247.536 238.464 247.632 ;
      RECT 0.216 248.304 238.464 248.400 ;
      RECT 0.216 249.072 238.464 249.168 ;
      RECT 0.216 249.840 238.464 249.936 ;
      RECT 0.216 250.608 238.464 250.704 ;
      RECT 0.216 251.376 238.464 251.472 ;
      RECT 0.216 252.144 238.464 252.240 ;
      RECT 0.216 252.912 238.464 253.008 ;
      RECT 0.216 253.680 238.464 253.776 ;
      RECT 0.216 254.448 238.464 254.544 ;
      RECT 0.216 255.216 238.464 255.312 ;
      RECT 0.216 255.984 238.464 256.080 ;
      RECT 0.216 256.752 238.464 256.848 ;
      RECT 0.216 257.520 238.464 257.616 ;
      RECT 0.216 258.288 238.464 258.384 ;
      RECT 0.216 259.056 238.464 259.152 ;
      RECT 0.216 259.824 238.464 259.920 ;
      RECT 0.216 260.592 238.464 260.688 ;
      RECT 0.216 261.360 238.464 261.456 ;
      RECT 0.216 262.128 238.464 262.224 ;
      RECT 0.216 262.896 238.464 262.992 ;
      RECT 0.216 263.664 238.464 263.760 ;
      RECT 0.216 264.432 238.464 264.528 ;
      RECT 0.216 265.200 238.464 265.296 ;
      RECT 0.216 265.968 238.464 266.064 ;
      RECT 0.216 266.736 238.464 266.832 ;
      RECT 0.216 267.504 238.464 267.600 ;
      RECT 0.216 268.272 238.464 268.368 ;
      RECT 0.216 269.040 238.464 269.136 ;
      RECT 0.216 269.808 238.464 269.904 ;
      RECT 0.216 270.576 238.464 270.672 ;
      RECT 0.216 271.344 238.464 271.440 ;
      RECT 0.216 272.112 238.464 272.208 ;
      RECT 0.216 272.880 238.464 272.976 ;
      RECT 0.216 273.648 238.464 273.744 ;
      RECT 0.216 274.416 238.464 274.512 ;
      RECT 0.216 275.184 238.464 275.280 ;
      RECT 0.216 275.952 238.464 276.048 ;
      RECT 0.216 276.720 238.464 276.816 ;
      RECT 0.216 277.488 238.464 277.584 ;
      RECT 0.216 278.256 238.464 278.352 ;
      RECT 0.216 279.024 238.464 279.120 ;
      RECT 0.216 279.792 238.464 279.888 ;
      RECT 0.216 280.560 238.464 280.656 ;
      RECT 0.216 281.328 238.464 281.424 ;
      RECT 0.216 282.096 238.464 282.192 ;
      RECT 0.216 282.864 238.464 282.960 ;
      RECT 0.216 283.632 238.464 283.728 ;
      RECT 0.216 284.400 238.464 284.496 ;
      RECT 0.216 285.168 238.464 285.264 ;
      RECT 0.216 285.936 238.464 286.032 ;
      RECT 0.216 286.704 238.464 286.800 ;
      RECT 0.216 287.472 238.464 287.568 ;
      RECT 0.216 288.240 238.464 288.336 ;
      RECT 0.216 289.008 238.464 289.104 ;
      RECT 0.216 289.776 238.464 289.872 ;
      RECT 0.216 290.544 238.464 290.640 ;
      RECT 0.216 291.312 238.464 291.408 ;
      RECT 0.216 292.080 238.464 292.176 ;
      RECT 0.216 292.848 238.464 292.944 ;
      RECT 0.216 293.616 238.464 293.712 ;
    END
  END VSS
  PIN VDD
    DIRECTION INOUT ;
    USE POWER ;
    PORT
      LAYER M4 ;
      RECT 0.216 0.624 238.464 0.720 ;
      RECT 0.216 1.392 238.464 1.488 ;
      RECT 0.216 2.160 238.464 2.256 ;
      RECT 0.216 2.928 238.464 3.024 ;
      RECT 0.216 3.696 238.464 3.792 ;
      RECT 0.216 4.464 238.464 4.560 ;
      RECT 0.216 5.232 238.464 5.328 ;
      RECT 0.216 6.000 238.464 6.096 ;
      RECT 0.216 6.768 238.464 6.864 ;
      RECT 0.216 7.536 238.464 7.632 ;
      RECT 0.216 8.304 238.464 8.400 ;
      RECT 0.216 9.072 238.464 9.168 ;
      RECT 0.216 9.840 238.464 9.936 ;
      RECT 0.216 10.608 238.464 10.704 ;
      RECT 0.216 11.376 238.464 11.472 ;
      RECT 0.216 12.144 238.464 12.240 ;
      RECT 0.216 12.912 238.464 13.008 ;
      RECT 0.216 13.680 238.464 13.776 ;
      RECT 0.216 14.448 238.464 14.544 ;
      RECT 0.216 15.216 238.464 15.312 ;
      RECT 0.216 15.984 238.464 16.080 ;
      RECT 0.216 16.752 238.464 16.848 ;
      RECT 0.216 17.520 238.464 17.616 ;
      RECT 0.216 18.288 238.464 18.384 ;
      RECT 0.216 19.056 238.464 19.152 ;
      RECT 0.216 19.824 238.464 19.920 ;
      RECT 0.216 20.592 238.464 20.688 ;
      RECT 0.216 21.360 238.464 21.456 ;
      RECT 0.216 22.128 238.464 22.224 ;
      RECT 0.216 22.896 238.464 22.992 ;
      RECT 0.216 23.664 238.464 23.760 ;
      RECT 0.216 24.432 238.464 24.528 ;
      RECT 0.216 25.200 238.464 25.296 ;
      RECT 0.216 25.968 238.464 26.064 ;
      RECT 0.216 26.736 238.464 26.832 ;
      RECT 0.216 27.504 238.464 27.600 ;
      RECT 0.216 28.272 238.464 28.368 ;
      RECT 0.216 29.040 238.464 29.136 ;
      RECT 0.216 29.808 238.464 29.904 ;
      RECT 0.216 30.576 238.464 30.672 ;
      RECT 0.216 31.344 238.464 31.440 ;
      RECT 0.216 32.112 238.464 32.208 ;
      RECT 0.216 32.880 238.464 32.976 ;
      RECT 0.216 33.648 238.464 33.744 ;
      RECT 0.216 34.416 238.464 34.512 ;
      RECT 0.216 35.184 238.464 35.280 ;
      RECT 0.216 35.952 238.464 36.048 ;
      RECT 0.216 36.720 238.464 36.816 ;
      RECT 0.216 37.488 238.464 37.584 ;
      RECT 0.216 38.256 238.464 38.352 ;
      RECT 0.216 39.024 238.464 39.120 ;
      RECT 0.216 39.792 238.464 39.888 ;
      RECT 0.216 40.560 238.464 40.656 ;
      RECT 0.216 41.328 238.464 41.424 ;
      RECT 0.216 42.096 238.464 42.192 ;
      RECT 0.216 42.864 238.464 42.960 ;
      RECT 0.216 43.632 238.464 43.728 ;
      RECT 0.216 44.400 238.464 44.496 ;
      RECT 0.216 45.168 238.464 45.264 ;
      RECT 0.216 45.936 238.464 46.032 ;
      RECT 0.216 46.704 238.464 46.800 ;
      RECT 0.216 47.472 238.464 47.568 ;
      RECT 0.216 48.240 238.464 48.336 ;
      RECT 0.216 49.008 238.464 49.104 ;
      RECT 0.216 49.776 238.464 49.872 ;
      RECT 0.216 50.544 238.464 50.640 ;
      RECT 0.216 51.312 238.464 51.408 ;
      RECT 0.216 52.080 238.464 52.176 ;
      RECT 0.216 52.848 238.464 52.944 ;
      RECT 0.216 53.616 238.464 53.712 ;
      RECT 0.216 54.384 238.464 54.480 ;
      RECT 0.216 55.152 238.464 55.248 ;
      RECT 0.216 55.920 238.464 56.016 ;
      RECT 0.216 56.688 238.464 56.784 ;
      RECT 0.216 57.456 238.464 57.552 ;
      RECT 0.216 58.224 238.464 58.320 ;
      RECT 0.216 58.992 238.464 59.088 ;
      RECT 0.216 59.760 238.464 59.856 ;
      RECT 0.216 60.528 238.464 60.624 ;
      RECT 0.216 61.296 238.464 61.392 ;
      RECT 0.216 62.064 238.464 62.160 ;
      RECT 0.216 62.832 238.464 62.928 ;
      RECT 0.216 63.600 238.464 63.696 ;
      RECT 0.216 64.368 238.464 64.464 ;
      RECT 0.216 65.136 238.464 65.232 ;
      RECT 0.216 65.904 238.464 66.000 ;
      RECT 0.216 66.672 238.464 66.768 ;
      RECT 0.216 67.440 238.464 67.536 ;
      RECT 0.216 68.208 238.464 68.304 ;
      RECT 0.216 68.976 238.464 69.072 ;
      RECT 0.216 69.744 238.464 69.840 ;
      RECT 0.216 70.512 238.464 70.608 ;
      RECT 0.216 71.280 238.464 71.376 ;
      RECT 0.216 72.048 238.464 72.144 ;
      RECT 0.216 72.816 238.464 72.912 ;
      RECT 0.216 73.584 238.464 73.680 ;
      RECT 0.216 74.352 238.464 74.448 ;
      RECT 0.216 75.120 238.464 75.216 ;
      RECT 0.216 75.888 238.464 75.984 ;
      RECT 0.216 76.656 238.464 76.752 ;
      RECT 0.216 77.424 238.464 77.520 ;
      RECT 0.216 78.192 238.464 78.288 ;
      RECT 0.216 78.960 238.464 79.056 ;
      RECT 0.216 79.728 238.464 79.824 ;
      RECT 0.216 80.496 238.464 80.592 ;
      RECT 0.216 81.264 238.464 81.360 ;
      RECT 0.216 82.032 238.464 82.128 ;
      RECT 0.216 82.800 238.464 82.896 ;
      RECT 0.216 83.568 238.464 83.664 ;
      RECT 0.216 84.336 238.464 84.432 ;
      RECT 0.216 85.104 238.464 85.200 ;
      RECT 0.216 85.872 238.464 85.968 ;
      RECT 0.216 86.640 238.464 86.736 ;
      RECT 0.216 87.408 238.464 87.504 ;
      RECT 0.216 88.176 238.464 88.272 ;
      RECT 0.216 88.944 238.464 89.040 ;
      RECT 0.216 89.712 238.464 89.808 ;
      RECT 0.216 90.480 238.464 90.576 ;
      RECT 0.216 91.248 238.464 91.344 ;
      RECT 0.216 92.016 238.464 92.112 ;
      RECT 0.216 92.784 238.464 92.880 ;
      RECT 0.216 93.552 238.464 93.648 ;
      RECT 0.216 94.320 238.464 94.416 ;
      RECT 0.216 95.088 238.464 95.184 ;
      RECT 0.216 95.856 238.464 95.952 ;
      RECT 0.216 96.624 238.464 96.720 ;
      RECT 0.216 97.392 238.464 97.488 ;
      RECT 0.216 98.160 238.464 98.256 ;
      RECT 0.216 98.928 238.464 99.024 ;
      RECT 0.216 99.696 238.464 99.792 ;
      RECT 0.216 100.464 238.464 100.560 ;
      RECT 0.216 101.232 238.464 101.328 ;
      RECT 0.216 102.000 238.464 102.096 ;
      RECT 0.216 102.768 238.464 102.864 ;
      RECT 0.216 103.536 238.464 103.632 ;
      RECT 0.216 104.304 238.464 104.400 ;
      RECT 0.216 105.072 238.464 105.168 ;
      RECT 0.216 105.840 238.464 105.936 ;
      RECT 0.216 106.608 238.464 106.704 ;
      RECT 0.216 107.376 238.464 107.472 ;
      RECT 0.216 108.144 238.464 108.240 ;
      RECT 0.216 108.912 238.464 109.008 ;
      RECT 0.216 109.680 238.464 109.776 ;
      RECT 0.216 110.448 238.464 110.544 ;
      RECT 0.216 111.216 238.464 111.312 ;
      RECT 0.216 111.984 238.464 112.080 ;
      RECT 0.216 112.752 238.464 112.848 ;
      RECT 0.216 113.520 238.464 113.616 ;
      RECT 0.216 114.288 238.464 114.384 ;
      RECT 0.216 115.056 238.464 115.152 ;
      RECT 0.216 115.824 238.464 115.920 ;
      RECT 0.216 116.592 238.464 116.688 ;
      RECT 0.216 117.360 238.464 117.456 ;
      RECT 0.216 118.128 238.464 118.224 ;
      RECT 0.216 118.896 238.464 118.992 ;
      RECT 0.216 119.664 238.464 119.760 ;
      RECT 0.216 120.432 238.464 120.528 ;
      RECT 0.216 121.200 238.464 121.296 ;
      RECT 0.216 121.968 238.464 122.064 ;
      RECT 0.216 122.736 238.464 122.832 ;
      RECT 0.216 123.504 238.464 123.600 ;
      RECT 0.216 124.272 238.464 124.368 ;
      RECT 0.216 125.040 238.464 125.136 ;
      RECT 0.216 125.808 238.464 125.904 ;
      RECT 0.216 126.576 238.464 126.672 ;
      RECT 0.216 127.344 238.464 127.440 ;
      RECT 0.216 128.112 238.464 128.208 ;
      RECT 0.216 128.880 238.464 128.976 ;
      RECT 0.216 129.648 238.464 129.744 ;
      RECT 0.216 130.416 238.464 130.512 ;
      RECT 0.216 131.184 238.464 131.280 ;
      RECT 0.216 131.952 238.464 132.048 ;
      RECT 0.216 132.720 238.464 132.816 ;
      RECT 0.216 133.488 238.464 133.584 ;
      RECT 0.216 134.256 238.464 134.352 ;
      RECT 0.216 135.024 238.464 135.120 ;
      RECT 0.216 135.792 238.464 135.888 ;
      RECT 0.216 136.560 238.464 136.656 ;
      RECT 0.216 137.328 238.464 137.424 ;
      RECT 0.216 138.096 238.464 138.192 ;
      RECT 0.216 138.864 238.464 138.960 ;
      RECT 0.216 139.632 238.464 139.728 ;
      RECT 0.216 140.400 238.464 140.496 ;
      RECT 0.216 141.168 238.464 141.264 ;
      RECT 0.216 141.936 238.464 142.032 ;
      RECT 0.216 142.704 238.464 142.800 ;
      RECT 0.216 143.472 238.464 143.568 ;
      RECT 0.216 144.240 238.464 144.336 ;
      RECT 0.216 145.008 238.464 145.104 ;
      RECT 0.216 145.776 238.464 145.872 ;
      RECT 0.216 146.544 238.464 146.640 ;
      RECT 0.216 147.312 238.464 147.408 ;
      RECT 0.216 148.080 238.464 148.176 ;
      RECT 0.216 148.848 238.464 148.944 ;
      RECT 0.216 149.616 238.464 149.712 ;
      RECT 0.216 150.384 238.464 150.480 ;
      RECT 0.216 151.152 238.464 151.248 ;
      RECT 0.216 151.920 238.464 152.016 ;
      RECT 0.216 152.688 238.464 152.784 ;
      RECT 0.216 153.456 238.464 153.552 ;
      RECT 0.216 154.224 238.464 154.320 ;
      RECT 0.216 154.992 238.464 155.088 ;
      RECT 0.216 155.760 238.464 155.856 ;
      RECT 0.216 156.528 238.464 156.624 ;
      RECT 0.216 157.296 238.464 157.392 ;
      RECT 0.216 158.064 238.464 158.160 ;
      RECT 0.216 158.832 238.464 158.928 ;
      RECT 0.216 159.600 238.464 159.696 ;
      RECT 0.216 160.368 238.464 160.464 ;
      RECT 0.216 161.136 238.464 161.232 ;
      RECT 0.216 161.904 238.464 162.000 ;
      RECT 0.216 162.672 238.464 162.768 ;
      RECT 0.216 163.440 238.464 163.536 ;
      RECT 0.216 164.208 238.464 164.304 ;
      RECT 0.216 164.976 238.464 165.072 ;
      RECT 0.216 165.744 238.464 165.840 ;
      RECT 0.216 166.512 238.464 166.608 ;
      RECT 0.216 167.280 238.464 167.376 ;
      RECT 0.216 168.048 238.464 168.144 ;
      RECT 0.216 168.816 238.464 168.912 ;
      RECT 0.216 169.584 238.464 169.680 ;
      RECT 0.216 170.352 238.464 170.448 ;
      RECT 0.216 171.120 238.464 171.216 ;
      RECT 0.216 171.888 238.464 171.984 ;
      RECT 0.216 172.656 238.464 172.752 ;
      RECT 0.216 173.424 238.464 173.520 ;
      RECT 0.216 174.192 238.464 174.288 ;
      RECT 0.216 174.960 238.464 175.056 ;
      RECT 0.216 175.728 238.464 175.824 ;
      RECT 0.216 176.496 238.464 176.592 ;
      RECT 0.216 177.264 238.464 177.360 ;
      RECT 0.216 178.032 238.464 178.128 ;
      RECT 0.216 178.800 238.464 178.896 ;
      RECT 0.216 179.568 238.464 179.664 ;
      RECT 0.216 180.336 238.464 180.432 ;
      RECT 0.216 181.104 238.464 181.200 ;
      RECT 0.216 181.872 238.464 181.968 ;
      RECT 0.216 182.640 238.464 182.736 ;
      RECT 0.216 183.408 238.464 183.504 ;
      RECT 0.216 184.176 238.464 184.272 ;
      RECT 0.216 184.944 238.464 185.040 ;
      RECT 0.216 185.712 238.464 185.808 ;
      RECT 0.216 186.480 238.464 186.576 ;
      RECT 0.216 187.248 238.464 187.344 ;
      RECT 0.216 188.016 238.464 188.112 ;
      RECT 0.216 188.784 238.464 188.880 ;
      RECT 0.216 189.552 238.464 189.648 ;
      RECT 0.216 190.320 238.464 190.416 ;
      RECT 0.216 191.088 238.464 191.184 ;
      RECT 0.216 191.856 238.464 191.952 ;
      RECT 0.216 192.624 238.464 192.720 ;
      RECT 0.216 193.392 238.464 193.488 ;
      RECT 0.216 194.160 238.464 194.256 ;
      RECT 0.216 194.928 238.464 195.024 ;
      RECT 0.216 195.696 238.464 195.792 ;
      RECT 0.216 196.464 238.464 196.560 ;
      RECT 0.216 197.232 238.464 197.328 ;
      RECT 0.216 198.000 238.464 198.096 ;
      RECT 0.216 198.768 238.464 198.864 ;
      RECT 0.216 199.536 238.464 199.632 ;
      RECT 0.216 200.304 238.464 200.400 ;
      RECT 0.216 201.072 238.464 201.168 ;
      RECT 0.216 201.840 238.464 201.936 ;
      RECT 0.216 202.608 238.464 202.704 ;
      RECT 0.216 203.376 238.464 203.472 ;
      RECT 0.216 204.144 238.464 204.240 ;
      RECT 0.216 204.912 238.464 205.008 ;
      RECT 0.216 205.680 238.464 205.776 ;
      RECT 0.216 206.448 238.464 206.544 ;
      RECT 0.216 207.216 238.464 207.312 ;
      RECT 0.216 207.984 238.464 208.080 ;
      RECT 0.216 208.752 238.464 208.848 ;
      RECT 0.216 209.520 238.464 209.616 ;
      RECT 0.216 210.288 238.464 210.384 ;
      RECT 0.216 211.056 238.464 211.152 ;
      RECT 0.216 211.824 238.464 211.920 ;
      RECT 0.216 212.592 238.464 212.688 ;
      RECT 0.216 213.360 238.464 213.456 ;
      RECT 0.216 214.128 238.464 214.224 ;
      RECT 0.216 214.896 238.464 214.992 ;
      RECT 0.216 215.664 238.464 215.760 ;
      RECT 0.216 216.432 238.464 216.528 ;
      RECT 0.216 217.200 238.464 217.296 ;
      RECT 0.216 217.968 238.464 218.064 ;
      RECT 0.216 218.736 238.464 218.832 ;
      RECT 0.216 219.504 238.464 219.600 ;
      RECT 0.216 220.272 238.464 220.368 ;
      RECT 0.216 221.040 238.464 221.136 ;
      RECT 0.216 221.808 238.464 221.904 ;
      RECT 0.216 222.576 238.464 222.672 ;
      RECT 0.216 223.344 238.464 223.440 ;
      RECT 0.216 224.112 238.464 224.208 ;
      RECT 0.216 224.880 238.464 224.976 ;
      RECT 0.216 225.648 238.464 225.744 ;
      RECT 0.216 226.416 238.464 226.512 ;
      RECT 0.216 227.184 238.464 227.280 ;
      RECT 0.216 227.952 238.464 228.048 ;
      RECT 0.216 228.720 238.464 228.816 ;
      RECT 0.216 229.488 238.464 229.584 ;
      RECT 0.216 230.256 238.464 230.352 ;
      RECT 0.216 231.024 238.464 231.120 ;
      RECT 0.216 231.792 238.464 231.888 ;
      RECT 0.216 232.560 238.464 232.656 ;
      RECT 0.216 233.328 238.464 233.424 ;
      RECT 0.216 234.096 238.464 234.192 ;
      RECT 0.216 234.864 238.464 234.960 ;
      RECT 0.216 235.632 238.464 235.728 ;
      RECT 0.216 236.400 238.464 236.496 ;
      RECT 0.216 237.168 238.464 237.264 ;
      RECT 0.216 237.936 238.464 238.032 ;
      RECT 0.216 238.704 238.464 238.800 ;
      RECT 0.216 239.472 238.464 239.568 ;
      RECT 0.216 240.240 238.464 240.336 ;
      RECT 0.216 241.008 238.464 241.104 ;
      RECT 0.216 241.776 238.464 241.872 ;
      RECT 0.216 242.544 238.464 242.640 ;
      RECT 0.216 243.312 238.464 243.408 ;
      RECT 0.216 244.080 238.464 244.176 ;
      RECT 0.216 244.848 238.464 244.944 ;
      RECT 0.216 245.616 238.464 245.712 ;
      RECT 0.216 246.384 238.464 246.480 ;
      RECT 0.216 247.152 238.464 247.248 ;
      RECT 0.216 247.920 238.464 248.016 ;
      RECT 0.216 248.688 238.464 248.784 ;
      RECT 0.216 249.456 238.464 249.552 ;
      RECT 0.216 250.224 238.464 250.320 ;
      RECT 0.216 250.992 238.464 251.088 ;
      RECT 0.216 251.760 238.464 251.856 ;
      RECT 0.216 252.528 238.464 252.624 ;
      RECT 0.216 253.296 238.464 253.392 ;
      RECT 0.216 254.064 238.464 254.160 ;
      RECT 0.216 254.832 238.464 254.928 ;
      RECT 0.216 255.600 238.464 255.696 ;
      RECT 0.216 256.368 238.464 256.464 ;
      RECT 0.216 257.136 238.464 257.232 ;
      RECT 0.216 257.904 238.464 258.000 ;
      RECT 0.216 258.672 238.464 258.768 ;
      RECT 0.216 259.440 238.464 259.536 ;
      RECT 0.216 260.208 238.464 260.304 ;
      RECT 0.216 260.976 238.464 261.072 ;
      RECT 0.216 261.744 238.464 261.840 ;
      RECT 0.216 262.512 238.464 262.608 ;
      RECT 0.216 263.280 238.464 263.376 ;
      RECT 0.216 264.048 238.464 264.144 ;
      RECT 0.216 264.816 238.464 264.912 ;
      RECT 0.216 265.584 238.464 265.680 ;
      RECT 0.216 266.352 238.464 266.448 ;
      RECT 0.216 267.120 238.464 267.216 ;
      RECT 0.216 267.888 238.464 267.984 ;
      RECT 0.216 268.656 238.464 268.752 ;
      RECT 0.216 269.424 238.464 269.520 ;
      RECT 0.216 270.192 238.464 270.288 ;
      RECT 0.216 270.960 238.464 271.056 ;
      RECT 0.216 271.728 238.464 271.824 ;
      RECT 0.216 272.496 238.464 272.592 ;
      RECT 0.216 273.264 238.464 273.360 ;
      RECT 0.216 274.032 238.464 274.128 ;
      RECT 0.216 274.800 238.464 274.896 ;
      RECT 0.216 275.568 238.464 275.664 ;
      RECT 0.216 276.336 238.464 276.432 ;
      RECT 0.216 277.104 238.464 277.200 ;
      RECT 0.216 277.872 238.464 277.968 ;
      RECT 0.216 278.640 238.464 278.736 ;
      RECT 0.216 279.408 238.464 279.504 ;
      RECT 0.216 280.176 238.464 280.272 ;
      RECT 0.216 280.944 238.464 281.040 ;
      RECT 0.216 281.712 238.464 281.808 ;
      RECT 0.216 282.480 238.464 282.576 ;
      RECT 0.216 283.248 238.464 283.344 ;
      RECT 0.216 284.016 238.464 284.112 ;
      RECT 0.216 284.784 238.464 284.880 ;
      RECT 0.216 285.552 238.464 285.648 ;
      RECT 0.216 286.320 238.464 286.416 ;
      RECT 0.216 287.088 238.464 287.184 ;
      RECT 0.216 287.856 238.464 287.952 ;
      RECT 0.216 288.624 238.464 288.720 ;
      RECT 0.216 289.392 238.464 289.488 ;
      RECT 0.216 290.160 238.464 290.256 ;
      RECT 0.216 290.928 238.464 291.024 ;
      RECT 0.216 291.696 238.464 291.792 ;
      RECT 0.216 292.464 238.464 292.560 ;
      RECT 0.216 293.232 238.464 293.328 ;
    END
  END VDD
  OBS
    LAYER M1 ;
    RECT 0 0 238.680 293.761 ;
    LAYER M2 ;
    RECT 0 0 238.680 293.761 ;
    LAYER M3 ;
    RECT 0 0 238.680 293.761 ;
    LAYER M4 ;
    RECT 0 0 238.680 293.761 ;
  END
END fakeram_1rw1r_130w1024d_sram

END LIBRARY
